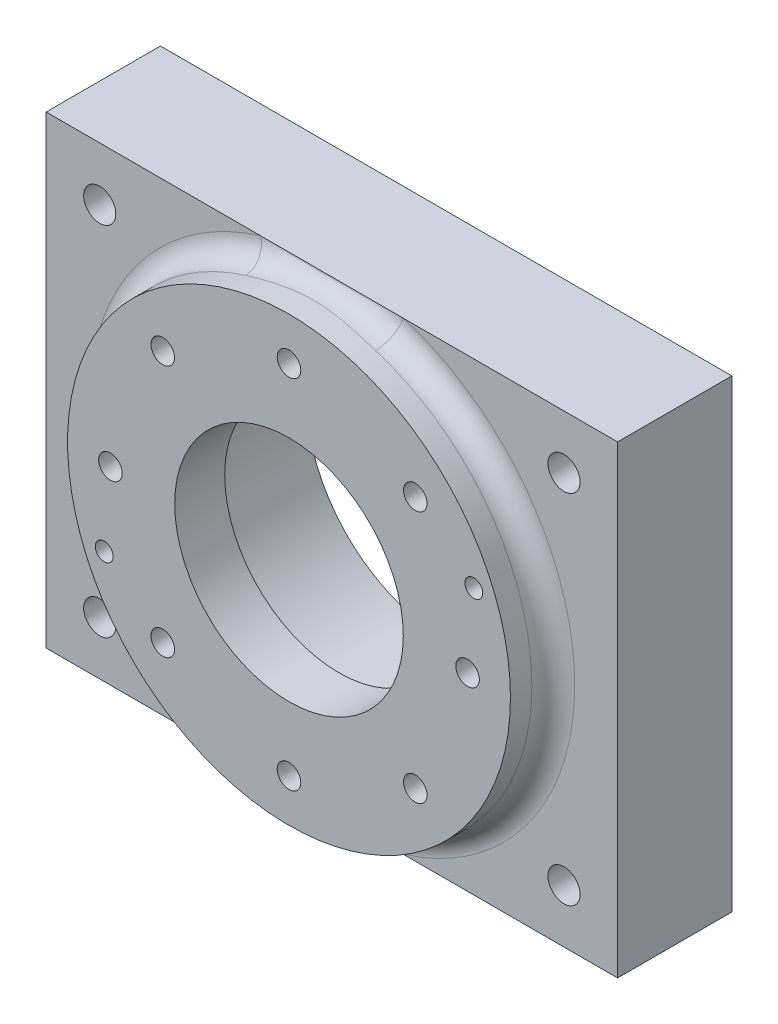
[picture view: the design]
ISO-10303-21;
HEADER;
FILE_DESCRIPTION(('STEP AP214'),'2;1');
FILE_NAME('part.step','',(''),(''),'','','');
FILE_SCHEMA(('AUTOMOTIVE_DESIGN { 1 0 10303 214 1 1 1 1 }'));
ENDSEC;
DATA;
#1=APPLICATION_CONTEXT('core data for automotive mechanical design processes');
#2=APPLICATION_PROTOCOL_DEFINITION('international standard','automotive_design',2000,#1);
#3=PRODUCT_CONTEXT('',#1,'mechanical');
#4=PRODUCT('Part','Part','',(#3));
#5=PRODUCT_RELATED_PRODUCT_CATEGORY('part','',(#4));
#6=PRODUCT_DEFINITION_FORMATION('','',#4);
#7=PRODUCT_DEFINITION_CONTEXT('part definition',#1,'design');
#8=PRODUCT_DEFINITION('design','',#6,#7);
#9=PRODUCT_DEFINITION_SHAPE('','',#8);
#10=(LENGTH_UNIT() NAMED_UNIT(*) SI_UNIT(.MILLI.,.METRE.));
#11=(NAMED_UNIT(*) PLANE_ANGLE_UNIT() SI_UNIT($,.RADIAN.));
#12=(NAMED_UNIT(*) SI_UNIT($,.STERADIAN.) SOLID_ANGLE_UNIT());
#13=UNCERTAINTY_MEASURE_WITH_UNIT(LENGTH_MEASURE(1.E-05),#10,'distance_accuracy_value','');
#14=(GEOMETRIC_REPRESENTATION_CONTEXT(3) GLOBAL_UNCERTAINTY_ASSIGNED_CONTEXT((#13)) GLOBAL_UNIT_ASSIGNED_CONTEXT((#10,
#11,#12)) REPRESENTATION_CONTEXT('',''));
#15=CARTESIAN_POINT('',(0.,0.,0.));
#16=DIRECTION('',(0.,0.,1.));
#17=DIRECTION('',(1.,0.,0.));
#18=AXIS2_PLACEMENT_3D('',#15,#16,#17);
#19=CARTESIAN_POINT('',(51.737253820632,21.430272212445,32.));
#20=DIRECTION('',(0.,0.,1.));
#21=DIRECTION('',(1.,0.,0.));
#22=AXIS2_PLACEMENT_3D('',#19,#20,#21);
#23=PLANE('',#22);
#24=CARTESIAN_POINT('',(51.737253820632,21.430272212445,32.));
#25=DIRECTION('',(0.,0.,1.));
#26=DIRECTION('',(1.,0.,0.));
#27=AXIS2_PLACEMENT_3D('',#24,#25,#26);
#28=CIRCLE('',#27,2.5);
#29=CARTESIAN_POINT('',(54.237253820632,21.430272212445,32.));
#30=VERTEX_POINT('',#29);
#31=EDGE_CURVE('E43',#30,#30,#28,.T.);
#32=ORIENTED_EDGE('',*,*,#31,.T.);
#33=EDGE_LOOP('',(#32));
#34=FACE_BOUND('',#33,.T.);
#35=ADVANCED_FACE('F15',(#34),#23,.T.);
#36=CARTESIAN_POINT('',(0.,0.,30.));
#37=DIRECTION('',(0.,0.,1.));
#38=DIRECTION('',(1.,0.,0.));
#39=AXIS2_PLACEMENT_3D('',#36,#37,#38);
#40=PLANE('',#39);
#41=CARTESIAN_POINT('',(0.,0.,30.));
#42=DIRECTION('',(0.,0.,1.));
#43=DIRECTION('',(1.,0.,0.));
#44=AXIS2_PLACEMENT_3D('',#41,#42,#43);
#45=CIRCLE('',#44,32.);
#46=CARTESIAN_POINT('',(32.,0.,30.));
#47=VERTEX_POINT('',#46);
#48=EDGE_CURVE('E363',#47,#47,#45,.T.);
#49=ORIENTED_EDGE('',*,*,#48,.T.);
#50=EDGE_LOOP('',(#49));
#51=FACE_BOUND('',#50,.T.);
#52=CARTESIAN_POINT('',(0.,0.,30.));
#53=DIRECTION('',(0.,0.,1.));
#54=DIRECTION('',(1.,0.,0.));
#55=AXIS2_PLACEMENT_3D('',#52,#53,#54);
#56=CIRCLE('',#55,39.003);
#57=CARTESIAN_POINT('',(39.003,0.,30.));
#58=VERTEX_POINT('',#57);
#59=EDGE_CURVE('E9',#58,#58,#56,.T.);
#60=ORIENTED_EDGE('',*,*,#59,.F.);
#61=EDGE_LOOP('',(#60));
#62=FACE_BOUND('',#61,.T.);
#63=ADVANCED_FACE('F875',(#51,#62),#40,.F.);
#64=CARTESIAN_POINT('',(-51.73725382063,-21.43027221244,32.));
#65=DIRECTION('',(0.,0.,1.));
#66=DIRECTION('',(1.,0.,0.));
#67=AXIS2_PLACEMENT_3D('',#64,#65,#66);
#68=PLANE('',#67);
#69=CARTESIAN_POINT('',(-51.73725382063,-21.43027221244,32.));
#70=DIRECTION('',(0.,0.,1.));
#71=DIRECTION('',(1.,0.,0.));
#72=AXIS2_PLACEMENT_3D('',#69,#70,#71);
#73=CIRCLE('',#72,2.5);
#74=CARTESIAN_POINT('',(-49.23725382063,-21.43027221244,32.));
#75=VERTEX_POINT('',#74);
#76=EDGE_CURVE('E131',#75,#75,#73,.T.);
#77=ORIENTED_EDGE('',*,*,#76,.T.);
#78=EDGE_LOOP('',(#77));
#79=FACE_BOUND('',#78,.T.);
#80=ADVANCED_FACE('F876',(#79),#68,.T.);
#81=CARTESIAN_POINT('',(0.,0.,26.));
#82=DIRECTION('',(0.,0.,1.));
#83=DIRECTION('',(1.,0.,0.));
#84=AXIS2_PLACEMENT_3D('',#81,#82,#83);
#85=CYLINDRICAL_SURFACE('',#84,39.003);
#86=DIRECTION('',(0.,0.,1.));
#87=VECTOR('',#86,1.);
#88=CARTESIAN_POINT('',(39.003,0.,26.));
#89=LINE('',#88,#87);
#90=CARTESIAN_POINT('',(39.003,0.,26.));
#91=VERTEX_POINT('',#90);
#92=EDGE_CURVE('E23',#91,#58,#89,.T.);
#93=ORIENTED_EDGE('',*,*,#92,.F.);
#94=CARTESIAN_POINT('',(0.,0.,26.));
#95=DIRECTION('',(0.,0.,1.));
#96=DIRECTION('',(1.,0.,0.));
#97=AXIS2_PLACEMENT_3D('',#94,#95,#96);
#98=CIRCLE('',#97,39.003);
#99=EDGE_CURVE('E293',#91,#91,#98,.T.);
#100=ORIENTED_EDGE('',*,*,#99,.F.);
#101=ORIENTED_EDGE('',*,*,#92,.T.);
#102=ORIENTED_EDGE('',*,*,#59,.T.);
#103=EDGE_LOOP('',(#93,#100,#101,#102));
#104=FACE_BOUND('',#103,.T.);
#105=ADVANCED_FACE('F882',(#104),#85,.F.);
#106=CARTESIAN_POINT('',(35.355339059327,35.355339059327,5.9));
#107=DIRECTION('',(0.,0.,1.));
#108=DIRECTION('',(1.,0.,0.));
#109=AXIS2_PLACEMENT_3D('',#106,#107,#108);
#110=CYLINDRICAL_SURFACE('',#109,3.3);
#111=CARTESIAN_POINT('',(35.355339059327,35.355339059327,6.1));
#112=DIRECTION('',(0.,0.,1.));
#113=DIRECTION('',(1.,0.,0.));
#114=AXIS2_PLACEMENT_3D('',#111,#112,#113);
#115=CIRCLE('',#114,3.3);
#116=CARTESIAN_POINT('',(38.655339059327,35.355339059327,6.1));
#117=VERTEX_POINT('',#116);
#118=EDGE_CURVE('E360',#117,#117,#115,.T.);
#119=ORIENTED_EDGE('',*,*,#118,.F.);
#120=DIRECTION('',(0.,0.,1.));
#121=VECTOR('',#120,1.);
#122=CARTESIAN_POINT('',(38.655339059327,35.355339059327,5.9));
#123=LINE('',#122,#121);
#124=CARTESIAN_POINT('',(38.655339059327,35.355339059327,44.));
#125=VERTEX_POINT('',#124);
#126=EDGE_CURVE('E142',#117,#125,#123,.T.);
#127=ORIENTED_EDGE('',*,*,#126,.T.);
#128=CARTESIAN_POINT('',(35.355339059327,35.355339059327,44.));
#129=DIRECTION('',(0.,0.,1.));
#130=DIRECTION('',(1.,0.,0.));
#131=AXIS2_PLACEMENT_3D('',#128,#129,#130);
#132=CIRCLE('',#131,3.3);
#133=EDGE_CURVE('E323',#125,#125,#132,.T.);
#134=ORIENTED_EDGE('',*,*,#133,.T.);
#135=ORIENTED_EDGE('',*,*,#126,.F.);
#136=EDGE_LOOP('',(#119,#127,#134,#135));
#137=FACE_BOUND('',#136,.T.);
#138=ADVANCED_FACE('F888',(#137),#110,.F.);
#139=CARTESIAN_POINT('',(51.737253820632,21.430272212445,32.));
#140=DIRECTION('',(0.,0.,1.));
#141=DIRECTION('',(1.,0.,0.));
#142=AXIS2_PLACEMENT_3D('',#139,#140,#141);
#143=CYLINDRICAL_SURFACE('',#142,2.5);
#144=DIRECTION('',(0.,0.,1.));
#145=VECTOR('',#144,1.);
#146=CARTESIAN_POINT('',(54.237253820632,21.430272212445,32.));
#147=LINE('',#146,#145);
#148=CARTESIAN_POINT('',(54.237253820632,21.430272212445,44.));
#149=VERTEX_POINT('',#148);
#150=EDGE_CURVE('E366',#30,#149,#147,.T.);
#151=ORIENTED_EDGE('',*,*,#150,.F.);
#152=ORIENTED_EDGE('',*,*,#31,.F.);
#153=ORIENTED_EDGE('',*,*,#150,.T.);
#154=CARTESIAN_POINT('',(51.737253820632,21.430272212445,44.));
#155=DIRECTION('',(0.,0.,1.));
#156=DIRECTION('',(1.,0.,0.));
#157=AXIS2_PLACEMENT_3D('',#154,#155,#156);
#158=CIRCLE('',#157,2.5);
#159=EDGE_CURVE('E330',#149,#149,#158,.T.);
#160=ORIENTED_EDGE('',*,*,#159,.T.);
#161=EDGE_LOOP('',(#151,#152,#153,#160));
#162=FACE_BOUND('',#161,.T.);
#163=ADVANCED_FACE('F883',(#162),#143,.F.);
#164=CARTESIAN_POINT('',(50.,0.,5.9));
#165=DIRECTION('',(0.,0.,1.));
#166=DIRECTION('',(1.,0.,0.));
#167=AXIS2_PLACEMENT_3D('',#164,#165,#166);
#168=CYLINDRICAL_SURFACE('',#167,3.3);
#169=CARTESIAN_POINT('',(50.,0.,6.1));
#170=DIRECTION('',(0.,0.,1.));
#171=DIRECTION('',(1.,0.,0.));
#172=AXIS2_PLACEMENT_3D('',#169,#170,#171);
#173=CIRCLE('',#172,3.3);
#174=CARTESIAN_POINT('',(53.3,0.,6.1));
#175=VERTEX_POINT('',#174);
#176=EDGE_CURVE('E300',#175,#175,#173,.T.);
#177=ORIENTED_EDGE('',*,*,#176,.F.);
#178=DIRECTION('',(0.,0.,1.));
#179=VECTOR('',#178,1.);
#180=CARTESIAN_POINT('',(53.3,0.,5.9));
#181=LINE('',#180,#179);
#182=CARTESIAN_POINT('',(53.3,0.,44.));
#183=VERTEX_POINT('',#182);
#184=EDGE_CURVE('E280',#175,#183,#181,.T.);
#185=ORIENTED_EDGE('',*,*,#184,.T.);
#186=CARTESIAN_POINT('',(50.,0.,44.));
#187=DIRECTION('',(0.,0.,1.));
#188=DIRECTION('',(1.,0.,0.));
#189=AXIS2_PLACEMENT_3D('',#186,#187,#188);
#190=CIRCLE('',#189,3.3);
#191=EDGE_CURVE('E321',#183,#183,#190,.T.);
#192=ORIENTED_EDGE('',*,*,#191,.T.);
#193=ORIENTED_EDGE('',*,*,#184,.F.);
#194=EDGE_LOOP('',(#177,#185,#192,#193));
#195=FACE_BOUND('',#194,.T.);
#196=ADVANCED_FACE('F889',(#195),#168,.F.);
#197=CARTESIAN_POINT('',(0.,50.,5.9));
#198=DIRECTION('',(0.,0.,1.));
#199=DIRECTION('',(1.,0.,0.));
#200=AXIS2_PLACEMENT_3D('',#197,#198,#199);
#201=CYLINDRICAL_SURFACE('',#200,3.3);
#202=CARTESIAN_POINT('',(0.,50.,6.1));
#203=DIRECTION('',(0.,0.,1.));
#204=DIRECTION('',(1.,0.,0.));
#205=AXIS2_PLACEMENT_3D('',#202,#203,#204);
#206=CIRCLE('',#205,3.3);
#207=CARTESIAN_POINT('',(3.3,50.,6.1));
#208=VERTEX_POINT('',#207);
#209=EDGE_CURVE('E352',#208,#208,#206,.T.);
#210=ORIENTED_EDGE('',*,*,#209,.F.);
#211=DIRECTION('',(0.,0.,1.));
#212=VECTOR('',#211,1.);
#213=CARTESIAN_POINT('',(3.3,50.,5.9));
#214=LINE('',#213,#212);
#215=CARTESIAN_POINT('',(3.3,50.,44.));
#216=VERTEX_POINT('',#215);
#217=EDGE_CURVE('E272',#208,#216,#214,.T.);
#218=ORIENTED_EDGE('',*,*,#217,.T.);
#219=CARTESIAN_POINT('',(0.,50.,44.));
#220=DIRECTION('',(0.,0.,1.));
#221=DIRECTION('',(1.,0.,0.));
#222=AXIS2_PLACEMENT_3D('',#219,#220,#221);
#223=CIRCLE('',#222,3.3);
#224=EDGE_CURVE('E320',#216,#216,#223,.T.);
#225=ORIENTED_EDGE('',*,*,#224,.T.);
#226=ORIENTED_EDGE('',*,*,#217,.F.);
#227=EDGE_LOOP('',(#210,#218,#225,#226));
#228=FACE_BOUND('',#227,.T.);
#229=ADVANCED_FACE('F893',(#228),#201,.F.);
#230=CARTESIAN_POINT('',(-35.35533905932,35.355339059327,5.9));
#231=DIRECTION('',(0.,0.,1.));
#232=DIRECTION('',(1.,0.,0.));
#233=AXIS2_PLACEMENT_3D('',#230,#231,#232);
#234=CYLINDRICAL_SURFACE('',#233,3.3);
#235=CARTESIAN_POINT('',(-35.35533905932,35.355339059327,6.1));
#236=DIRECTION('',(0.,0.,1.));
#237=DIRECTION('',(1.,0.,0.));
#238=AXIS2_PLACEMENT_3D('',#235,#236,#237);
#239=CIRCLE('',#238,3.3);
#240=CARTESIAN_POINT('',(-32.05533905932,35.355339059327,6.1));
#241=VERTEX_POINT('',#240);
#242=EDGE_CURVE('E297',#241,#241,#239,.T.);
#243=ORIENTED_EDGE('',*,*,#242,.F.);
#244=DIRECTION('',(0.,0.,1.));
#245=VECTOR('',#244,1.);
#246=CARTESIAN_POINT('',(-32.05533905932,35.355339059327,5.9));
#247=LINE('',#246,#245);
#248=CARTESIAN_POINT('',(-32.05533905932,35.355339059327,44.));
#249=VERTEX_POINT('',#248);
#250=EDGE_CURVE('E279',#241,#249,#247,.T.);
#251=ORIENTED_EDGE('',*,*,#250,.T.);
#252=CARTESIAN_POINT('',(-35.35533905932,35.355339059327,44.));
#253=DIRECTION('',(0.,0.,1.));
#254=DIRECTION('',(1.,0.,0.));
#255=AXIS2_PLACEMENT_3D('',#252,#253,#254);
#256=CIRCLE('',#255,3.3);
#257=EDGE_CURVE('E325',#249,#249,#256,.T.);
#258=ORIENTED_EDGE('',*,*,#257,.T.);
#259=ORIENTED_EDGE('',*,*,#250,.F.);
#260=EDGE_LOOP('',(#243,#251,#258,#259));
#261=FACE_BOUND('',#260,.T.);
#262=ADVANCED_FACE('F890',(#261),#234,.F.);
#263=CARTESIAN_POINT('',(0.,0.,30.));
#264=DIRECTION('',(0.,0.,1.));
#265=DIRECTION('',(1.,0.,0.));
#266=AXIS2_PLACEMENT_3D('',#263,#264,#265);
#267=CYLINDRICAL_SURFACE('',#266,32.);
#268=DIRECTION('',(0.,0.,1.));
#269=VECTOR('',#268,1.);
#270=CARTESIAN_POINT('',(32.,0.,30.));
#271=LINE('',#270,#269);
#272=CARTESIAN_POINT('',(32.,0.,44.));
#273=VERTEX_POINT('',#272);
#274=EDGE_CURVE('E365',#47,#273,#271,.T.);
#275=ORIENTED_EDGE('',*,*,#274,.F.);
#276=ORIENTED_EDGE('',*,*,#48,.F.);
#277=ORIENTED_EDGE('',*,*,#274,.T.);
#278=CARTESIAN_POINT('',(0.,0.,44.));
#279=DIRECTION('',(0.,0.,1.));
#280=DIRECTION('',(1.,0.,0.));
#281=AXIS2_PLACEMENT_3D('',#278,#279,#280);
#282=CIRCLE('',#281,32.);
#283=EDGE_CURVE('E316',#273,#273,#282,.T.);
#284=ORIENTED_EDGE('',*,*,#283,.T.);
#285=EDGE_LOOP('',(#275,#276,#277,#284));
#286=FACE_BOUND('',#285,.T.);
#287=ADVANCED_FACE('F434',(#286),#267,.F.);
#288=CARTESIAN_POINT('',(-50.,0.,5.9));
#289=DIRECTION('',(0.,0.,1.));
#290=DIRECTION('',(1.,0.,0.));
#291=AXIS2_PLACEMENT_3D('',#288,#289,#290);
#292=CYLINDRICAL_SURFACE('',#291,3.3);
#293=CARTESIAN_POINT('',(-50.,0.,6.1));
#294=DIRECTION('',(0.,0.,1.));
#295=DIRECTION('',(1.,0.,0.));
#296=AXIS2_PLACEMENT_3D('',#293,#294,#295);
#297=CIRCLE('',#296,3.3);
#298=CARTESIAN_POINT('',(-46.7,0.,6.1));
#299=VERTEX_POINT('',#298);
#300=EDGE_CURVE('E338',#299,#299,#297,.T.);
#301=ORIENTED_EDGE('',*,*,#300,.F.);
#302=DIRECTION('',(0.,0.,1.));
#303=VECTOR('',#302,1.);
#304=CARTESIAN_POINT('',(-46.7,0.,5.9));
#305=LINE('',#304,#303);
#306=CARTESIAN_POINT('',(-46.7,0.,44.));
#307=VERTEX_POINT('',#306);
#308=EDGE_CURVE('E343',#299,#307,#305,.T.);
#309=ORIENTED_EDGE('',*,*,#308,.T.);
#310=CARTESIAN_POINT('',(-50.,0.,44.));
#311=DIRECTION('',(0.,0.,1.));
#312=DIRECTION('',(1.,0.,0.));
#313=AXIS2_PLACEMENT_3D('',#310,#311,#312);
#314=CIRCLE('',#313,3.3);
#315=EDGE_CURVE('E307',#307,#307,#314,.T.);
#316=ORIENTED_EDGE('',*,*,#315,.T.);
#317=ORIENTED_EDGE('',*,*,#308,.F.);
#318=EDGE_LOOP('',(#301,#309,#316,#317));
#319=FACE_BOUND('',#318,.T.);
#320=ADVANCED_FACE('F896',(#319),#292,.F.);
#321=CARTESIAN_POINT('',(35.355339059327,-35.35533905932,5.9));
#322=DIRECTION('',(0.,0.,1.));
#323=DIRECTION('',(1.,0.,0.));
#324=AXIS2_PLACEMENT_3D('',#321,#322,#323);
#325=CYLINDRICAL_SURFACE('',#324,3.3);
#326=CARTESIAN_POINT('',(35.355339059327,-35.35533905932,6.1));
#327=DIRECTION('',(0.,0.,1.));
#328=DIRECTION('',(1.,0.,0.));
#329=AXIS2_PLACEMENT_3D('',#326,#327,#328);
#330=CIRCLE('',#329,3.3);
#331=CARTESIAN_POINT('',(38.655339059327,-35.35533905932,6.1));
#332=VERTEX_POINT('',#331);
#333=EDGE_CURVE('E333',#332,#332,#330,.T.);
#334=ORIENTED_EDGE('',*,*,#333,.F.);
#335=DIRECTION('',(0.,0.,1.));
#336=VECTOR('',#335,1.);
#337=CARTESIAN_POINT('',(38.655339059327,-35.35533905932,5.9));
#338=LINE('',#337,#336);
#339=CARTESIAN_POINT('',(38.655339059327,-35.35533905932,44.));
#340=VERTEX_POINT('',#339);
#341=EDGE_CURVE('E340',#332,#340,#338,.T.);
#342=ORIENTED_EDGE('',*,*,#341,.T.);
#343=CARTESIAN_POINT('',(35.355339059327,-35.35533905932,44.));
#344=DIRECTION('',(0.,0.,1.));
#345=DIRECTION('',(1.,0.,0.));
#346=AXIS2_PLACEMENT_3D('',#343,#344,#345);
#347=CIRCLE('',#346,3.3);
#348=EDGE_CURVE('E304',#340,#340,#347,.T.);
#349=ORIENTED_EDGE('',*,*,#348,.T.);
#350=ORIENTED_EDGE('',*,*,#341,.F.);
#351=EDGE_LOOP('',(#334,#342,#349,#350));
#352=FACE_BOUND('',#351,.T.);
#353=ADVANCED_FACE('F899',(#352),#325,.F.);
#354=CARTESIAN_POINT('',(-51.73725382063,-21.43027221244,32.));
#355=DIRECTION('',(0.,0.,1.));
#356=DIRECTION('',(1.,0.,0.));
#357=AXIS2_PLACEMENT_3D('',#354,#355,#356);
#358=CYLINDRICAL_SURFACE('',#357,2.5);
#359=DIRECTION('',(0.,0.,1.));
#360=VECTOR('',#359,1.);
#361=CARTESIAN_POINT('',(-49.23725382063,-21.43027221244,32.));
#362=LINE('',#361,#360);
#363=CARTESIAN_POINT('',(-49.23725382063,-21.43027221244,44.));
#364=VERTEX_POINT('',#363);
#365=EDGE_CURVE('E310',#75,#364,#362,.T.);
#366=ORIENTED_EDGE('',*,*,#365,.F.);
#367=ORIENTED_EDGE('',*,*,#76,.F.);
#368=ORIENTED_EDGE('',*,*,#365,.T.);
#369=CARTESIAN_POINT('',(-51.73725382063,-21.43027221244,44.));
#370=DIRECTION('',(0.,0.,1.));
#371=DIRECTION('',(1.,0.,0.));
#372=AXIS2_PLACEMENT_3D('',#369,#370,#371);
#373=CIRCLE('',#372,2.5);
#374=EDGE_CURVE('E306',#364,#364,#373,.T.);
#375=ORIENTED_EDGE('',*,*,#374,.T.);
#376=EDGE_LOOP('',(#366,#367,#368,#375));
#377=FACE_BOUND('',#376,.T.);
#378=ADVANCED_FACE('F903',(#377),#358,.F.);
#379=CARTESIAN_POINT('',(0.,-50.,5.9));
#380=DIRECTION('',(0.,0.,1.));
#381=DIRECTION('',(1.,0.,0.));
#382=AXIS2_PLACEMENT_3D('',#379,#380,#381);
#383=CYLINDRICAL_SURFACE('',#382,3.3);
#384=CARTESIAN_POINT('',(0.,-50.,6.1));
#385=DIRECTION('',(0.,0.,1.));
#386=DIRECTION('',(1.,0.,0.));
#387=AXIS2_PLACEMENT_3D('',#384,#385,#386);
#388=CIRCLE('',#387,3.3);
#389=CARTESIAN_POINT('',(3.3,-50.,6.1));
#390=VERTEX_POINT('',#389);
#391=EDGE_CURVE('E332',#390,#390,#388,.T.);
#392=ORIENTED_EDGE('',*,*,#391,.F.);
#393=DIRECTION('',(0.,0.,1.));
#394=VECTOR('',#393,1.);
#395=CARTESIAN_POINT('',(3.3,-50.,5.9));
#396=LINE('',#395,#394);
#397=CARTESIAN_POINT('',(3.3,-50.,44.));
#398=VERTEX_POINT('',#397);
#399=EDGE_CURVE('E315',#390,#398,#396,.T.);
#400=ORIENTED_EDGE('',*,*,#399,.T.);
#401=CARTESIAN_POINT('',(0.,-50.,44.));
#402=DIRECTION('',(0.,0.,1.));
#403=DIRECTION('',(1.,0.,0.));
#404=AXIS2_PLACEMENT_3D('',#401,#402,#403);
#405=CIRCLE('',#404,3.3);
#406=EDGE_CURVE('E454',#398,#398,#405,.T.);
#407=ORIENTED_EDGE('',*,*,#406,.T.);
#408=ORIENTED_EDGE('',*,*,#399,.F.);
#409=EDGE_LOOP('',(#392,#400,#407,#408));
#410=FACE_BOUND('',#409,.T.);
#411=ADVANCED_FACE('F909',(#410),#383,.F.);
#412=CARTESIAN_POINT('',(-35.35533905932,-35.35533905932,5.9));
#413=DIRECTION('',(0.,0.,1.));
#414=DIRECTION('',(1.,0.,0.));
#415=AXIS2_PLACEMENT_3D('',#412,#413,#414);
#416=CYLINDRICAL_SURFACE('',#415,3.3);
#417=CARTESIAN_POINT('',(-35.35533905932,-35.35533905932,6.1));
#418=DIRECTION('',(0.,0.,1.));
#419=DIRECTION('',(1.,0.,0.));
#420=AXIS2_PLACEMENT_3D('',#417,#418,#419);
#421=CIRCLE('',#420,3.3);
#422=CARTESIAN_POINT('',(-32.05533905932,-35.35533905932,6.1));
#423=VERTEX_POINT('',#422);
#424=EDGE_CURVE('E326',#423,#423,#421,.T.);
#425=ORIENTED_EDGE('',*,*,#424,.F.);
#426=DIRECTION('',(0.,0.,1.));
#427=VECTOR('',#426,1.);
#428=CARTESIAN_POINT('',(-32.05533905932,-35.35533905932,5.9));
#429=LINE('',#428,#427);
#430=CARTESIAN_POINT('',(-32.05533905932,-35.35533905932,44.));
#431=VERTEX_POINT('',#430);
#432=EDGE_CURVE('E358',#423,#431,#429,.T.);
#433=ORIENTED_EDGE('',*,*,#432,.T.);
#434=CARTESIAN_POINT('',(-35.35533905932,-35.35533905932,44.));
#435=DIRECTION('',(0.,0.,1.));
#436=DIRECTION('',(1.,0.,0.));
#437=AXIS2_PLACEMENT_3D('',#434,#435,#436);
#438=CIRCLE('',#437,3.3);
#439=EDGE_CURVE('E305',#431,#431,#438,.T.);
#440=ORIENTED_EDGE('',*,*,#439,.T.);
#441=ORIENTED_EDGE('',*,*,#432,.F.);
#442=EDGE_LOOP('',(#425,#433,#440,#441));
#443=FACE_BOUND('',#442,.T.);
#444=ADVANCED_FACE('F911',(#443),#416,.F.);
#445=CARTESIAN_POINT('',(35.355339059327,35.355339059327,6.1));
#446=DIRECTION('',(0.,0.,1.));
#447=DIRECTION('',(1.,0.,0.));
#448=AXIS2_PLACEMENT_3D('',#445,#446,#447);
#449=PLANE('',#448);
#450=ORIENTED_EDGE('',*,*,#118,.T.);
#451=EDGE_LOOP('',(#450));
#452=FACE_BOUND('',#451,.T.);
#453=CARTESIAN_POINT('',(35.355339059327,35.355339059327,6.1));
#454=DIRECTION('',(0.,0.,1.));
#455=DIRECTION('',(1.,0.,0.));
#456=AXIS2_PLACEMENT_3D('',#453,#454,#455);
#457=CIRCLE('',#456,5.5);
#458=CARTESIAN_POINT('',(40.855339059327,35.355339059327,6.1));
#459=VERTEX_POINT('',#458);
#460=EDGE_CURVE('E298',#459,#459,#457,.T.);
#461=ORIENTED_EDGE('',*,*,#460,.F.);
#462=EDGE_LOOP('',(#461));
#463=FACE_BOUND('',#462,.T.);
#464=ADVANCED_FACE('F918',(#452,#463),#449,.F.);
#465=CARTESIAN_POINT('',(0.,50.,6.1));
#466=DIRECTION('',(0.,0.,1.));
#467=DIRECTION('',(1.,0.,0.));
#468=AXIS2_PLACEMENT_3D('',#465,#466,#467);
#469=PLANE('',#468);
#470=ORIENTED_EDGE('',*,*,#209,.T.);
#471=EDGE_LOOP('',(#470));
#472=FACE_BOUND('',#471,.T.);
#473=CARTESIAN_POINT('',(0.,50.,6.1));
#474=DIRECTION('',(0.,0.,1.));
#475=DIRECTION('',(1.,0.,0.));
#476=AXIS2_PLACEMENT_3D('',#473,#474,#475);
#477=CIRCLE('',#476,5.5);
#478=CARTESIAN_POINT('',(5.5,50.,6.1));
#479=VERTEX_POINT('',#478);
#480=EDGE_CURVE('E276',#479,#479,#477,.T.);
#481=ORIENTED_EDGE('',*,*,#480,.F.);
#482=EDGE_LOOP('',(#481));
#483=FACE_BOUND('',#482,.T.);
#484=ADVANCED_FACE('F968',(#472,#483),#469,.F.);
#485=CARTESIAN_POINT('',(16.838071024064,40.650699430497,12.));
#486=DIRECTION('',(0.,0.,1.));
#487=DIRECTION('',(1.,0.,0.));
#488=AXIS2_PLACEMENT_3D('',#485,#486,#487);
#489=PLANE('',#488);
#490=CARTESIAN_POINT('',(16.838071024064,40.650699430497,12.));
#491=DIRECTION('',(0.,0.,1.));
#492=DIRECTION('',(1.,0.,0.));
#493=AXIS2_PLACEMENT_3D('',#490,#491,#492);
#494=CIRCLE('',#493,1.65);
#495=CARTESIAN_POINT('',(18.488071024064,40.650699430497,12.));
#496=VERTEX_POINT('',#495);
#497=EDGE_CURVE('E288',#496,#496,#494,.T.);
#498=ORIENTED_EDGE('',*,*,#497,.F.);
#499=EDGE_LOOP('',(#498));
#500=FACE_BOUND('',#499,.T.);
#501=ADVANCED_FACE('F925',(#500),#489,.F.);
#502=CARTESIAN_POINT('',(40.650699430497,16.838071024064,12.));
#503=DIRECTION('',(0.,0.,1.));
#504=DIRECTION('',(1.,0.,0.));
#505=AXIS2_PLACEMENT_3D('',#502,#503,#504);
#506=PLANE('',#505);
#507=CARTESIAN_POINT('',(40.650699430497,16.838071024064,12.));
#508=DIRECTION('',(0.,0.,1.));
#509=DIRECTION('',(1.,0.,0.));
#510=AXIS2_PLACEMENT_3D('',#507,#508,#509);
#511=CIRCLE('',#510,1.65);
#512=CARTESIAN_POINT('',(42.300699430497,16.838071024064,12.));
#513=VERTEX_POINT('',#512);
#514=EDGE_CURVE('E287',#513,#513,#511,.T.);
#515=ORIENTED_EDGE('',*,*,#514,.F.);
#516=EDGE_LOOP('',(#515));
#517=FACE_BOUND('',#516,.T.);
#518=ADVANCED_FACE('F916',(#517),#506,.F.);
#519=CARTESIAN_POINT('',(50.,0.,6.1));
#520=DIRECTION('',(0.,0.,1.));
#521=DIRECTION('',(1.,0.,0.));
#522=AXIS2_PLACEMENT_3D('',#519,#520,#521);
#523=PLANE('',#522);
#524=ORIENTED_EDGE('',*,*,#176,.T.);
#525=EDGE_LOOP('',(#524));
#526=FACE_BOUND('',#525,.T.);
#527=CARTESIAN_POINT('',(50.,0.,6.1));
#528=DIRECTION('',(0.,0.,1.));
#529=DIRECTION('',(1.,0.,0.));
#530=AXIS2_PLACEMENT_3D('',#527,#528,#529);
#531=CIRCLE('',#530,5.5);
#532=CARTESIAN_POINT('',(55.5,0.,6.1));
#533=VERTEX_POINT('',#532);
#534=EDGE_CURVE('E497',#533,#533,#531,.T.);
#535=ORIENTED_EDGE('',*,*,#534,.F.);
#536=EDGE_LOOP('',(#535));
#537=FACE_BOUND('',#536,.T.);
#538=ADVANCED_FACE('F921',(#526,#537),#523,.F.);
#539=CARTESIAN_POINT('',(0.,0.,26.));
#540=DIRECTION('',(0.,0.,1.));
#541=DIRECTION('',(1.,0.,0.));
#542=AXIS2_PLACEMENT_3D('',#539,#540,#541);
#543=PLANE('',#542);
#544=ORIENTED_EDGE('',*,*,#99,.T.);
#545=EDGE_LOOP('',(#544));
#546=FACE_BOUND('',#545,.T.);
#547=CARTESIAN_POINT('',(0.,0.,26.));
#548=DIRECTION('',(0.,0.,1.));
#549=DIRECTION('',(1.,0.,0.));
#550=AXIS2_PLACEMENT_3D('',#547,#548,#549);
#551=CIRCLE('',#550,39.1);
#552=CARTESIAN_POINT('',(39.1,0.,26.));
#553=VERTEX_POINT('',#552);
#554=EDGE_CURVE('E267',#553,#553,#551,.T.);
#555=ORIENTED_EDGE('',*,*,#554,.F.);
#556=EDGE_LOOP('',(#555));
#557=FACE_BOUND('',#556,.T.);
#558=ADVANCED_FACE('F922',(#546,#557),#543,.F.);
#559=CARTESIAN_POINT('',(-16.83807102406,40.650699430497,12.));
#560=DIRECTION('',(0.,0.,1.));
#561=DIRECTION('',(1.,0.,0.));
#562=AXIS2_PLACEMENT_3D('',#559,#560,#561);
#563=PLANE('',#562);
#564=CARTESIAN_POINT('',(-16.83807102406,40.650699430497,12.));
#565=DIRECTION('',(0.,0.,1.));
#566=DIRECTION('',(1.,0.,0.));
#567=AXIS2_PLACEMENT_3D('',#564,#565,#566);
#568=CIRCLE('',#567,1.65);
#569=CARTESIAN_POINT('',(-15.18807102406,40.650699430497,12.));
#570=VERTEX_POINT('',#569);
#571=EDGE_CURVE('E261',#570,#570,#568,.T.);
#572=ORIENTED_EDGE('',*,*,#571,.F.);
#573=EDGE_LOOP('',(#572));
#574=FACE_BOUND('',#573,.T.);
#575=ADVANCED_FACE('F930',(#574),#563,.F.);
#576=CARTESIAN_POINT('',(-35.35533905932,35.355339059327,6.1));
#577=DIRECTION('',(0.,0.,1.));
#578=DIRECTION('',(1.,0.,0.));
#579=AXIS2_PLACEMENT_3D('',#576,#577,#578);
#580=PLANE('',#579);
#581=ORIENTED_EDGE('',*,*,#242,.T.);
#582=EDGE_LOOP('',(#581));
#583=FACE_BOUND('',#582,.T.);
#584=CARTESIAN_POINT('',(-35.35533905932,35.355339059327,6.1));
#585=DIRECTION('',(0.,0.,1.));
#586=DIRECTION('',(1.,0.,0.));
#587=AXIS2_PLACEMENT_3D('',#584,#585,#586);
#588=CIRCLE('',#587,5.5);
#589=CARTESIAN_POINT('',(-29.85533905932,35.355339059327,6.1));
#590=VERTEX_POINT('',#589);
#591=EDGE_CURVE('E247',#590,#590,#588,.T.);
#592=ORIENTED_EDGE('',*,*,#591,.F.);
#593=EDGE_LOOP('',(#592));
#594=FACE_BOUND('',#593,.T.);
#595=ADVANCED_FACE('F931',(#583,#594),#580,.F.);
#596=CARTESIAN_POINT('',(-40.65069943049,16.838071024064,12.));
#597=DIRECTION('',(0.,0.,1.));
#598=DIRECTION('',(1.,0.,0.));
#599=AXIS2_PLACEMENT_3D('',#596,#597,#598);
#600=PLANE('',#599);
#601=CARTESIAN_POINT('',(-40.65069943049,16.838071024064,12.));
#602=DIRECTION('',(0.,0.,1.));
#603=DIRECTION('',(1.,0.,0.));
#604=AXIS2_PLACEMENT_3D('',#601,#602,#603);
#605=CIRCLE('',#604,1.65);
#606=CARTESIAN_POINT('',(-39.00069943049,16.838071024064,12.));
#607=VERTEX_POINT('',#606);
#608=EDGE_CURVE('E237',#607,#607,#605,.T.);
#609=ORIENTED_EDGE('',*,*,#608,.F.);
#610=EDGE_LOOP('',(#609));
#611=FACE_BOUND('',#610,.T.);
#612=ADVANCED_FACE('F934',(#611),#600,.F.);
#613=CARTESIAN_POINT('',(-50.,0.,6.1));
#614=DIRECTION('',(0.,0.,1.));
#615=DIRECTION('',(1.,0.,0.));
#616=AXIS2_PLACEMENT_3D('',#613,#614,#615);
#617=PLANE('',#616);
#618=ORIENTED_EDGE('',*,*,#300,.T.);
#619=EDGE_LOOP('',(#618));
#620=FACE_BOUND('',#619,.T.);
#621=CARTESIAN_POINT('',(-50.,0.,6.1));
#622=DIRECTION('',(0.,0.,1.));
#623=DIRECTION('',(1.,0.,0.));
#624=AXIS2_PLACEMENT_3D('',#621,#622,#623);
#625=CIRCLE('',#624,5.5);
#626=CARTESIAN_POINT('',(-44.5,0.,6.1));
#627=VERTEX_POINT('',#626);
#628=EDGE_CURVE('E389',#627,#627,#625,.T.);
#629=ORIENTED_EDGE('',*,*,#628,.F.);
#630=EDGE_LOOP('',(#629));
#631=FACE_BOUND('',#630,.T.);
#632=ADVANCED_FACE('F936',(#620,#631),#617,.F.);
#633=CARTESIAN_POINT('',(40.650699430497,-16.83807102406,12.));
#634=DIRECTION('',(0.,0.,1.));
#635=DIRECTION('',(1.,0.,0.));
#636=AXIS2_PLACEMENT_3D('',#633,#634,#635);
#637=PLANE('',#636);
#638=CARTESIAN_POINT('',(40.650699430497,-16.83807102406,12.));
#639=DIRECTION('',(0.,0.,1.));
#640=DIRECTION('',(1.,0.,0.));
#641=AXIS2_PLACEMENT_3D('',#638,#639,#640);
#642=CIRCLE('',#641,1.65);
#643=CARTESIAN_POINT('',(42.300699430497,-16.83807102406,12.));
#644=VERTEX_POINT('',#643);
#645=EDGE_CURVE('E398',#644,#644,#642,.T.);
#646=ORIENTED_EDGE('',*,*,#645,.F.);
#647=EDGE_LOOP('',(#646));
#648=FACE_BOUND('',#647,.T.);
#649=ADVANCED_FACE('F944',(#648),#637,.F.);
#650=CARTESIAN_POINT('',(35.355339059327,-35.35533905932,6.1));
#651=DIRECTION('',(0.,0.,1.));
#652=DIRECTION('',(1.,0.,0.));
#653=AXIS2_PLACEMENT_3D('',#650,#651,#652);
#654=PLANE('',#653);
#655=ORIENTED_EDGE('',*,*,#333,.T.);
#656=EDGE_LOOP('',(#655));
#657=FACE_BOUND('',#656,.T.);
#658=CARTESIAN_POINT('',(35.355339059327,-35.35533905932,6.1));
#659=DIRECTION('',(0.,0.,1.));
#660=DIRECTION('',(1.,0.,0.));
#661=AXIS2_PLACEMENT_3D('',#658,#659,#660);
#662=CIRCLE('',#661,5.5);
#663=CARTESIAN_POINT('',(40.855339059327,-35.35533905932,6.1));
#664=VERTEX_POINT('',#663);
#665=EDGE_CURVE('E419',#664,#664,#662,.T.);
#666=ORIENTED_EDGE('',*,*,#665,.F.);
#667=EDGE_LOOP('',(#666));
#668=FACE_BOUND('',#667,.T.);
#669=ADVANCED_FACE('F949',(#657,#668),#654,.F.);
#670=CARTESIAN_POINT('',(16.838071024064,-40.65069943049,12.));
#671=DIRECTION('',(0.,0.,1.));
#672=DIRECTION('',(1.,0.,0.));
#673=AXIS2_PLACEMENT_3D('',#670,#671,#672);
#674=PLANE('',#673);
#675=CARTESIAN_POINT('',(16.838071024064,-40.65069943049,12.));
#676=DIRECTION('',(0.,0.,1.));
#677=DIRECTION('',(1.,0.,0.));
#678=AXIS2_PLACEMENT_3D('',#675,#676,#677);
#679=CIRCLE('',#678,1.65);
#680=CARTESIAN_POINT('',(18.488071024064,-40.65069943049,12.));
#681=VERTEX_POINT('',#680);
#682=EDGE_CURVE('E407',#681,#681,#679,.T.);
#683=ORIENTED_EDGE('',*,*,#682,.F.);
#684=EDGE_LOOP('',(#683));
#685=FACE_BOUND('',#684,.T.);
#686=ADVANCED_FACE('F866',(#685),#674,.F.);
#687=CARTESIAN_POINT('',(-40.65069943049,-16.83807102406,12.));
#688=DIRECTION('',(0.,0.,1.));
#689=DIRECTION('',(1.,0.,0.));
#690=AXIS2_PLACEMENT_3D('',#687,#688,#689);
#691=PLANE('',#690);
#692=CARTESIAN_POINT('',(-40.65069943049,-16.83807102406,12.));
#693=DIRECTION('',(0.,0.,1.));
#694=DIRECTION('',(1.,0.,0.));
#695=AXIS2_PLACEMENT_3D('',#692,#693,#694);
#696=CIRCLE('',#695,1.65);
#697=CARTESIAN_POINT('',(-39.00069943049,-16.83807102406,12.));
#698=VERTEX_POINT('',#697);
#699=EDGE_CURVE('E408',#698,#698,#696,.T.);
#700=ORIENTED_EDGE('',*,*,#699,.F.);
#701=EDGE_LOOP('',(#700));
#702=FACE_BOUND('',#701,.T.);
#703=ADVANCED_FACE('F857',(#702),#691,.F.);
#704=CARTESIAN_POINT('',(-16.83807102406,-40.65069943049,12.));
#705=DIRECTION('',(0.,0.,1.));
#706=DIRECTION('',(1.,0.,0.));
#707=AXIS2_PLACEMENT_3D('',#704,#705,#706);
#708=PLANE('',#707);
#709=CARTESIAN_POINT('',(-16.83807102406,-40.65069943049,12.));
#710=DIRECTION('',(0.,0.,1.));
#711=DIRECTION('',(1.,0.,0.));
#712=AXIS2_PLACEMENT_3D('',#709,#710,#711);
#713=CIRCLE('',#712,1.65);
#714=CARTESIAN_POINT('',(-15.18807102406,-40.65069943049,12.));
#715=VERTEX_POINT('',#714);
#716=EDGE_CURVE('E403',#715,#715,#713,.T.);
#717=ORIENTED_EDGE('',*,*,#716,.F.);
#718=EDGE_LOOP('',(#717));
#719=FACE_BOUND('',#718,.T.);
#720=ADVANCED_FACE('F851',(#719),#708,.F.);
#721=CARTESIAN_POINT('',(0.,-50.,6.1));
#722=DIRECTION('',(0.,0.,1.));
#723=DIRECTION('',(1.,0.,0.));
#724=AXIS2_PLACEMENT_3D('',#721,#722,#723);
#725=PLANE('',#724);
#726=ORIENTED_EDGE('',*,*,#391,.T.);
#727=EDGE_LOOP('',(#726));
#728=FACE_BOUND('',#727,.T.);
#729=CARTESIAN_POINT('',(0.,-50.,6.1));
#730=DIRECTION('',(0.,0.,1.));
#731=DIRECTION('',(1.,0.,0.));
#732=AXIS2_PLACEMENT_3D('',#729,#730,#731);
#733=CIRCLE('',#732,5.5);
#734=CARTESIAN_POINT('',(5.5,-50.,6.1));
#735=VERTEX_POINT('',#734);
#736=EDGE_CURVE('E394',#735,#735,#733,.T.);
#737=ORIENTED_EDGE('',*,*,#736,.F.);
#738=EDGE_LOOP('',(#737));
#739=FACE_BOUND('',#738,.T.);
#740=ADVANCED_FACE('F858',(#728,#739),#725,.F.);
#741=CARTESIAN_POINT('',(-35.35533905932,-35.35533905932,6.1));
#742=DIRECTION('',(0.,0.,1.));
#743=DIRECTION('',(1.,0.,0.));
#744=AXIS2_PLACEMENT_3D('',#741,#742,#743);
#745=PLANE('',#744);
#746=ORIENTED_EDGE('',*,*,#424,.T.);
#747=EDGE_LOOP('',(#746));
#748=FACE_BOUND('',#747,.T.);
#749=CARTESIAN_POINT('',(-35.35533905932,-35.35533905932,6.1));
#750=DIRECTION('',(0.,0.,1.));
#751=DIRECTION('',(1.,0.,0.));
#752=AXIS2_PLACEMENT_3D('',#749,#750,#751);
#753=CIRCLE('',#752,5.5);
#754=CARTESIAN_POINT('',(-29.85533905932,-35.35533905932,6.1));
#755=VERTEX_POINT('',#754);
#756=EDGE_CURVE('E383',#755,#755,#753,.T.);
#757=ORIENTED_EDGE('',*,*,#756,.F.);
#758=EDGE_LOOP('',(#757));
#759=FACE_BOUND('',#758,.T.);
#760=ADVANCED_FACE('F445',(#748,#759),#745,.F.);
#761=CARTESIAN_POINT('',(0.,0.,44.));
#762=DIRECTION('',(0.,0.,1.));
#763=DIRECTION('',(1.,0.,0.));
#764=AXIS2_PLACEMENT_3D('',#761,#762,#763);
#765=PLANE('',#764);
#766=ORIENTED_EDGE('',*,*,#133,.F.);
#767=EDGE_LOOP('',(#766));
#768=FACE_BOUND('',#767,.T.);
#769=ORIENTED_EDGE('',*,*,#159,.F.);
#770=EDGE_LOOP('',(#769));
#771=FACE_BOUND('',#770,.T.);
#772=ORIENTED_EDGE('',*,*,#191,.F.);
#773=EDGE_LOOP('',(#772));
#774=FACE_BOUND('',#773,.T.);
#775=ORIENTED_EDGE('',*,*,#224,.F.);
#776=EDGE_LOOP('',(#775));
#777=FACE_BOUND('',#776,.T.);
#778=ORIENTED_EDGE('',*,*,#257,.F.);
#779=EDGE_LOOP('',(#778));
#780=FACE_BOUND('',#779,.T.);
#781=ORIENTED_EDGE('',*,*,#283,.F.);
#782=EDGE_LOOP('',(#781));
#783=FACE_BOUND('',#782,.T.);
#784=ORIENTED_EDGE('',*,*,#315,.F.);
#785=EDGE_LOOP('',(#784));
#786=FACE_BOUND('',#785,.T.);
#787=ORIENTED_EDGE('',*,*,#348,.F.);
#788=EDGE_LOOP('',(#787));
#789=FACE_BOUND('',#788,.T.);
#790=ORIENTED_EDGE('',*,*,#374,.F.);
#791=EDGE_LOOP('',(#790));
#792=FACE_BOUND('',#791,.T.);
#793=ORIENTED_EDGE('',*,*,#406,.F.);
#794=EDGE_LOOP('',(#793));
#795=FACE_BOUND('',#794,.T.);
#796=ORIENTED_EDGE('',*,*,#439,.F.);
#797=EDGE_LOOP('',(#796));
#798=FACE_BOUND('',#797,.T.);
#799=CARTESIAN_POINT('',(0.,0.,44.));
#800=DIRECTION('',(0.,0.,1.));
#801=DIRECTION('',(1.,0.,0.));
#802=AXIS2_PLACEMENT_3D('',#799,#800,#801);
#803=CIRCLE('',#802,62.);
#804=CARTESIAN_POINT('',(62.,0.,44.));
#805=VERTEX_POINT('',#804);
#806=EDGE_CURVE('E459',#805,#805,#803,.T.);
#807=ORIENTED_EDGE('',*,*,#806,.T.);
#808=EDGE_LOOP('',(#807));
#809=FACE_BOUND('',#808,.T.);
#810=ADVANCED_FACE('F437',(#768,#771,#774,#777,#780,#783,#786,#789,#792,#795,#798,#809),#765,.T.);
#811=CARTESIAN_POINT('',(18.212485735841,59.264705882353,38.));
#812=CARTESIAN_POINT('',(14.678563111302,60.35070663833,38.));
#813=CARTESIAN_POINT('',(11.072687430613,61.202567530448,37.713108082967));
#814=CARTESIAN_POINT('',(7.412310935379,61.814925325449,37.381306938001));
#815=CARTESIAN_POINT('',(3.715342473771,62.183903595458,37.100373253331));
#816=CARTESIAN_POINT('',(7.593925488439E-13,62.307157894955,36.924679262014));
#817=CARTESIAN_POINT('',(-3.715342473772,62.183903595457,37.100373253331));
#818=CARTESIAN_POINT('',(-7.412310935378,61.814925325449,37.381306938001));
#819=CARTESIAN_POINT('',(-11.07268743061,61.202567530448,37.713108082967));
#820=CARTESIAN_POINT('',(-14.6785631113,60.35070663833,38.));
#821=CARTESIAN_POINT('',(-18.21248573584,59.264705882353,38.));
#822=CARTESIAN_POINT('',(18.212485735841,59.264705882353,32.));
#823=CARTESIAN_POINT('',(15.011002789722,60.248545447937,33.128852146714));
#824=CARTESIAN_POINT('',(11.408617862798,61.1365528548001,33.61290290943));
#825=CARTESIAN_POINT('',(7.690166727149,61.781787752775,33.764650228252));
#826=CARTESIAN_POINT('',(3.855528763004,62.191216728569,33.781440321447));
#827=CARTESIAN_POINT('',(2.46881233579E-13,62.315841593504,33.713484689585));
#828=CARTESIAN_POINT('',(-3.855528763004,62.191216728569,33.781440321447));
#829=CARTESIAN_POINT('',(-7.69016672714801,61.7817877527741,33.764650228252));
#830=CARTESIAN_POINT('',(-11.40861786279,61.1365528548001,33.61290290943));
#831=CARTESIAN_POINT('',(-15.01100278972,60.248545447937,33.128852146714));
#832=CARTESIAN_POINT('',(-18.21248573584,59.264705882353,32.));
#833=CARTESIAN_POINT('',(19.974984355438,65.,32.));
#834=CARTESIAN_POINT('',(15.733036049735,65.,32.));
#835=CARTESIAN_POINT('',(11.663825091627,65.,32.));
#836=CARTESIAN_POINT('',(7.713585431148,65.,32.));
#837=CARTESIAN_POINT('',(3.838562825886,65.,31.999999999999));
#838=CARTESIAN_POINT('',(-7.585043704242E-13,64.999999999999,32.000000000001));
#839=CARTESIAN_POINT('',(-3.838562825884,65.,31.999999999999));
#840=CARTESIAN_POINT('',(-7.713585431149,65.,32.));
#841=CARTESIAN_POINT('',(-11.66382509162,65.,32.));
#842=CARTESIAN_POINT('',(-15.73303604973,65.,32.));
#843=CARTESIAN_POINT('',(-19.97498435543,65.,32.));
#844=(BOUNDED_SURFACE() B_SPLINE_SURFACE(2,10,((#811,#812,#813,#814,#815,#816,#817,#818,#819,
#820,#821),(#822,#823,#824,#825,#826,#827,#828,#829,#830,#831,#832),(#833,#834,#835,#836,#837,
#838,#839,#840,#841,#842,#843)),.UNSPECIFIED.,.F.,.F.,.F.) B_SPLINE_SURFACE_WITH_KNOTS((3,3),
(11,11),(0.,36.970267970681),(78.904238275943,115.87450624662),
.UNSPECIFIED.) GEOMETRIC_REPRESENTATION_ITEM() RATIONAL_B_SPLINE_SURFACE(((1.,1.,1.,1.,1.,1.,1.,
1.,1.,1.,1.),(0.707106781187,0.780532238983,0.826675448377,0.858068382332,0.874709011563,
0.88123116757,0.874709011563,0.858068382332,0.826675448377,0.780532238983,0.707106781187),(1.,
1.,1.,1.,1.,1.,1.,1.,1.,1.,1.))) REPRESENTATION_ITEM('') SURFACE());
#845=CARTESIAN_POINT('',(19.974984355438,65.,38.));
#846=DIRECTION('',(-0.955882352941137,0.293749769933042,0.));
#847=DIRECTION('',(0.293749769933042,0.955882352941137,0.));
#848=AXIS2_PLACEMENT_3D('',#845,#846,#847);
#849=CIRCLE('',#848,6.);
#850=CARTESIAN_POINT('',(19.974984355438,65.,32.));
#851=VERTEX_POINT('',#850);
#852=CARTESIAN_POINT('',(18.212485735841,59.264705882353,38.));
#853=VERTEX_POINT('',#852);
#854=EDGE_CURVE('E640',#851,#853,#849,.T.);
#855=CARTESIAN_POINT('',(19.974984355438,65.,32.));
#856=CARTESIAN_POINT('',(15.733036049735,65.,32.));
#857=CARTESIAN_POINT('',(11.663825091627,65.,32.));
#858=CARTESIAN_POINT('',(7.713585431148,65.,32.));
#859=CARTESIAN_POINT('',(3.838562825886,65.,31.999999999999));
#860=CARTESIAN_POINT('',(-7.585043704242E-13,64.999999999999,32.000000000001));
#861=CARTESIAN_POINT('',(-3.838562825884,65.,31.999999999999));
#862=CARTESIAN_POINT('',(-7.713585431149,65.,32.));
#863=CARTESIAN_POINT('',(-11.66382509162,65.,32.));
#864=CARTESIAN_POINT('',(-15.73303604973,65.,32.));
#865=CARTESIAN_POINT('',(-19.97498435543,65.,32.));
#866=(BOUNDED_CURVE() B_SPLINE_CURVE(10,(#855,#856,#857,#858,#859,#860,#861,#862,#863,#864,
#865),.UNSPECIFIED.,.F.,.F.) B_SPLINE_CURVE_WITH_KNOTS((11,11),(78.904238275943,
115.87450624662),
.UNSPECIFIED.) CURVE() GEOMETRIC_REPRESENTATION_ITEM() RATIONAL_B_SPLINE_CURVE((1.,1.,1.,1.,1.,
1.,1.,1.,1.,1.,1.)) REPRESENTATION_ITEM(''));
#867=CARTESIAN_POINT('',(-19.97498435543,65.,32.));
#868=VERTEX_POINT('',#867);
#869=EDGE_CURVE('E584',#851,#868,#866,.T.);
#870=CARTESIAN_POINT('',(-19.97498435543,65.,32.));
#871=CARTESIAN_POINT('',(-18.21248573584,59.264705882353,32.));
#872=CARTESIAN_POINT('',(-18.21248573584,59.264705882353,38.));
#873=(BOUNDED_CURVE() B_SPLINE_CURVE(2,(#870,#871,#872),.UNSPECIFIED.,.F.,
.F.) B_SPLINE_CURVE_WITH_KNOTS((3,3),(0.,36.970267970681),
.UNSPECIFIED.) CURVE() GEOMETRIC_REPRESENTATION_ITEM() RATIONAL_B_SPLINE_CURVE((1.,
0.707106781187,1.)) REPRESENTATION_ITEM(''));
#874=CARTESIAN_POINT('',(-18.21248573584,59.264705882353,38.));
#875=VERTEX_POINT('',#874);
#876=EDGE_CURVE('E591',#868,#875,#873,.T.);
#877=CARTESIAN_POINT('',(18.212485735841,59.264705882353,38.));
#878=CARTESIAN_POINT('',(14.678563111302,60.35070663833,38.));
#879=CARTESIAN_POINT('',(11.072687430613,61.202567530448,37.713108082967));
#880=CARTESIAN_POINT('',(7.412310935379,61.814925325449,37.381306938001));
#881=CARTESIAN_POINT('',(3.715342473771,62.183903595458,37.100373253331));
#882=CARTESIAN_POINT('',(7.593925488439E-13,62.307157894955,36.924679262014));
#883=CARTESIAN_POINT('',(-3.715342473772,62.183903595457,37.100373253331));
#884=CARTESIAN_POINT('',(-7.412310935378,61.814925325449,37.381306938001));
#885=CARTESIAN_POINT('',(-11.07268743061,61.202567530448,37.713108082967));
#886=CARTESIAN_POINT('',(-14.6785631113,60.35070663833,38.));
#887=CARTESIAN_POINT('',(-18.21248573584,59.264705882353,38.));
#888=(BOUNDED_CURVE() B_SPLINE_CURVE(10,(#877,#878,#879,#880,#881,#882,#883,#884,#885,#886,
#887),.UNSPECIFIED.,.F.,.F.) B_SPLINE_CURVE_WITH_KNOTS((11,11),(78.904238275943,
115.87450624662),
.UNSPECIFIED.) CURVE() GEOMETRIC_REPRESENTATION_ITEM() RATIONAL_B_SPLINE_CURVE((1.,1.,1.,1.,1.,
1.,1.,1.,1.,1.,1.)) REPRESENTATION_ITEM(''));
#889=EDGE_CURVE('E471',#853,#875,#888,.T.);
#890=ORIENTED_EDGE('',*,*,#854,.F.);
#891=ORIENTED_EDGE('',*,*,#869,.T.);
#892=ORIENTED_EDGE('',*,*,#876,.T.);
#893=ORIENTED_EDGE('',*,*,#889,.F.);
#894=EDGE_LOOP('',(#890,#891,#892,#893));
#895=FACE_BOUND('',#894,.T.);
#896=ADVANCED_FACE('F442',(#895),#844,.T.);
#897=CARTESIAN_POINT('',(35.355339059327,35.355339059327,-0.1));
#898=DIRECTION('',(0.,0.,1.));
#899=DIRECTION('',(1.,0.,0.));
#900=AXIS2_PLACEMENT_3D('',#897,#898,#899);
#901=CYLINDRICAL_SURFACE('',#900,5.5);
#902=CARTESIAN_POINT('',(35.355339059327,35.355339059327,0.));
#903=DIRECTION('',(0.,0.,1.));
#904=DIRECTION('',(1.,0.,0.));
#905=AXIS2_PLACEMENT_3D('',#902,#903,#904);
#906=CIRCLE('',#905,5.5);
#907=CARTESIAN_POINT('',(40.855339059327,35.355339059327,0.));
#908=VERTEX_POINT('',#907);
#909=EDGE_CURVE('E563',#908,#908,#906,.T.);
#910=ORIENTED_EDGE('',*,*,#909,.F.);
#911=DIRECTION('',(0.,0.,1.));
#912=VECTOR('',#911,1.);
#913=CARTESIAN_POINT('',(40.855339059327,35.355339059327,-0.1));
#914=LINE('',#913,#912);
#915=EDGE_CURVE('E282',#908,#459,#914,.T.);
#916=ORIENTED_EDGE('',*,*,#915,.T.);
#917=ORIENTED_EDGE('',*,*,#460,.T.);
#918=ORIENTED_EDGE('',*,*,#915,.F.);
#919=EDGE_LOOP('',(#910,#916,#917,#918));
#920=FACE_BOUND('',#919,.T.);
#921=ADVANCED_FACE('F961',(#920),#901,.F.);
#922=CARTESIAN_POINT('',(0.,50.,-0.1));
#923=DIRECTION('',(0.,0.,1.));
#924=DIRECTION('',(1.,0.,0.));
#925=AXIS2_PLACEMENT_3D('',#922,#923,#924);
#926=CYLINDRICAL_SURFACE('',#925,5.5);
#927=CARTESIAN_POINT('',(0.,50.,0.));
#928=DIRECTION('',(0.,0.,1.));
#929=DIRECTION('',(1.,0.,0.));
#930=AXIS2_PLACEMENT_3D('',#927,#928,#929);
#931=CIRCLE('',#930,5.5);
#932=CARTESIAN_POINT('',(5.5,50.,0.));
#933=VERTEX_POINT('',#932);
#934=EDGE_CURVE('E597',#933,#933,#931,.T.);
#935=ORIENTED_EDGE('',*,*,#934,.F.);
#936=DIRECTION('',(0.,0.,1.));
#937=VECTOR('',#936,1.);
#938=CARTESIAN_POINT('',(5.5,50.,-0.1));
#939=LINE('',#938,#937);
#940=EDGE_CURVE('E284',#933,#479,#939,.T.);
#941=ORIENTED_EDGE('',*,*,#940,.T.);
#942=ORIENTED_EDGE('',*,*,#480,.T.);
#943=ORIENTED_EDGE('',*,*,#940,.F.);
#944=EDGE_LOOP('',(#935,#941,#942,#943));
#945=FACE_BOUND('',#944,.T.);
#946=ADVANCED_FACE('F980',(#945),#926,.F.);
#947=CARTESIAN_POINT('',(16.838071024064,40.650699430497,0.));
#948=DIRECTION('',(0.,0.,1.));
#949=DIRECTION('',(1.,0.,0.));
#950=AXIS2_PLACEMENT_3D('',#947,#948,#949);
#951=CYLINDRICAL_SURFACE('',#950,1.65);
#952=DIRECTION('',(0.,0.,1.));
#953=VECTOR('',#952,1.);
#954=CARTESIAN_POINT('',(18.488071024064,40.650699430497,0.));
#955=LINE('',#954,#953);
#956=CARTESIAN_POINT('',(18.488071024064,40.650699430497,0.));
#957=VERTEX_POINT('',#956);
#958=EDGE_CURVE('E283',#957,#496,#955,.T.);
#959=ORIENTED_EDGE('',*,*,#958,.F.);
#960=CARTESIAN_POINT('',(16.838071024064,40.650699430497,0.));
#961=DIRECTION('',(0.,0.,1.));
#962=DIRECTION('',(1.,0.,0.));
#963=AXIS2_PLACEMENT_3D('',#960,#961,#962);
#964=CIRCLE('',#963,1.65);
#965=EDGE_CURVE('E598',#957,#957,#964,.T.);
#966=ORIENTED_EDGE('',*,*,#965,.F.);
#967=ORIENTED_EDGE('',*,*,#958,.T.);
#968=ORIENTED_EDGE('',*,*,#497,.T.);
#969=EDGE_LOOP('',(#959,#966,#967,#968));
#970=FACE_BOUND('',#969,.T.);
#971=ADVANCED_FACE('F977',(#970),#951,.F.);
#972=CARTESIAN_POINT('',(40.650699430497,16.838071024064,0.));
#973=DIRECTION('',(0.,0.,1.));
#974=DIRECTION('',(1.,0.,0.));
#975=AXIS2_PLACEMENT_3D('',#972,#973,#974);
#976=CYLINDRICAL_SURFACE('',#975,1.65);
#977=DIRECTION('',(0.,0.,1.));
#978=VECTOR('',#977,1.);
#979=CARTESIAN_POINT('',(42.300699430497,16.838071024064,0.));
#980=LINE('',#979,#978);
#981=CARTESIAN_POINT('',(42.300699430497,16.838071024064,0.));
#982=VERTEX_POINT('',#981);
#983=EDGE_CURVE('E546',#982,#513,#980,.T.);
#984=ORIENTED_EDGE('',*,*,#983,.F.);
#985=CARTESIAN_POINT('',(40.650699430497,16.838071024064,0.));
#986=DIRECTION('',(0.,0.,1.));
#987=DIRECTION('',(1.,0.,0.));
#988=AXIS2_PLACEMENT_3D('',#985,#986,#987);
#989=CIRCLE('',#988,1.65);
#990=EDGE_CURVE('E582',#982,#982,#989,.T.);
#991=ORIENTED_EDGE('',*,*,#990,.F.);
#992=ORIENTED_EDGE('',*,*,#983,.T.);
#993=ORIENTED_EDGE('',*,*,#514,.T.);
#994=EDGE_LOOP('',(#984,#991,#992,#993));
#995=FACE_BOUND('',#994,.T.);
#996=ADVANCED_FACE('F985',(#995),#976,.F.);
#997=CARTESIAN_POINT('',(50.,0.,-0.1));
#998=DIRECTION('',(0.,0.,1.));
#999=DIRECTION('',(1.,0.,0.));
#1000=AXIS2_PLACEMENT_3D('',#997,#998,#999);
#1001=CYLINDRICAL_SURFACE('',#1000,5.5);
#1002=CARTESIAN_POINT('',(50.,0.,0.));
#1003=DIRECTION('',(0.,0.,1.));
#1004=DIRECTION('',(1.,0.,0.));
#1005=AXIS2_PLACEMENT_3D('',#1002,#1003,#1004);
#1006=CIRCLE('',#1005,5.5);
#1007=CARTESIAN_POINT('',(55.5,0.,0.));
#1008=VERTEX_POINT('',#1007);
#1009=EDGE_CURVE('E579',#1008,#1008,#1006,.T.);
#1010=ORIENTED_EDGE('',*,*,#1009,.F.);
#1011=DIRECTION('',(0.,0.,1.));
#1012=VECTOR('',#1011,1.);
#1013=CARTESIAN_POINT('',(55.5,0.,-0.1));
#1014=LINE('',#1013,#1012);
#1015=EDGE_CURVE('E275',#1008,#533,#1014,.T.);
#1016=ORIENTED_EDGE('',*,*,#1015,.T.);
#1017=ORIENTED_EDGE('',*,*,#534,.T.);
#1018=ORIENTED_EDGE('',*,*,#1015,.F.);
#1019=EDGE_LOOP('',(#1010,#1016,#1017,#1018));
#1020=FACE_BOUND('',#1019,.T.);
#1021=ADVANCED_FACE('F986',(#1020),#1001,.F.);
#1022=CARTESIAN_POINT('',(0.,0.,0.));
#1023=DIRECTION('',(0.,0.,1.));
#1024=DIRECTION('',(1.,0.,0.));
#1025=AXIS2_PLACEMENT_3D('',#1022,#1023,#1024);
#1026=CYLINDRICAL_SURFACE('',#1025,39.1);
#1027=DIRECTION('',(0.,0.,1.));
#1028=VECTOR('',#1027,1.);
#1029=CARTESIAN_POINT('',(39.1,0.,0.));
#1030=LINE('',#1029,#1028);
#1031=CARTESIAN_POINT('',(39.1,0.,0.));
#1032=VERTEX_POINT('',#1031);
#1033=EDGE_CURVE('E266',#1032,#553,#1030,.T.);
#1034=ORIENTED_EDGE('',*,*,#1033,.F.);
#1035=CARTESIAN_POINT('',(0.,0.,0.));
#1036=DIRECTION('',(0.,0.,1.));
#1037=DIRECTION('',(1.,0.,0.));
#1038=AXIS2_PLACEMENT_3D('',#1035,#1036,#1037);
#1039=CIRCLE('',#1038,39.1);
#1040=EDGE_CURVE('E573',#1032,#1032,#1039,.T.);
#1041=ORIENTED_EDGE('',*,*,#1040,.F.);
#1042=ORIENTED_EDGE('',*,*,#1033,.T.);
#1043=ORIENTED_EDGE('',*,*,#554,.T.);
#1044=EDGE_LOOP('',(#1034,#1041,#1042,#1043));
#1045=FACE_BOUND('',#1044,.T.);
#1046=ADVANCED_FACE('F989',(#1045),#1026,.F.);
#1047=CARTESIAN_POINT('',(-16.83807102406,40.650699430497,0.));
#1048=DIRECTION('',(0.,0.,1.));
#1049=DIRECTION('',(1.,0.,0.));
#1050=AXIS2_PLACEMENT_3D('',#1047,#1048,#1049);
#1051=CYLINDRICAL_SURFACE('',#1050,1.65);
#1052=DIRECTION('',(0.,0.,1.));
#1053=VECTOR('',#1052,1.);
#1054=CARTESIAN_POINT('',(-15.18807102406,40.650699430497,0.));
#1055=LINE('',#1054,#1053);
#1056=CARTESIAN_POINT('',(-15.18807102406,40.650699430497,0.));
#1057=VERTEX_POINT('',#1056);
#1058=EDGE_CURVE('E255',#1057,#570,#1055,.T.);
#1059=ORIENTED_EDGE('',*,*,#1058,.F.);
#1060=CARTESIAN_POINT('',(-16.83807102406,40.650699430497,0.));
#1061=DIRECTION('',(0.,0.,1.));
#1062=DIRECTION('',(1.,0.,0.));
#1063=AXIS2_PLACEMENT_3D('',#1060,#1061,#1062);
#1064=CIRCLE('',#1063,1.65);
#1065=EDGE_CURVE('E566',#1057,#1057,#1064,.T.);
#1066=ORIENTED_EDGE('',*,*,#1065,.F.);
#1067=ORIENTED_EDGE('',*,*,#1058,.T.);
#1068=ORIENTED_EDGE('',*,*,#571,.T.);
#1069=EDGE_LOOP('',(#1059,#1066,#1067,#1068));
#1070=FACE_BOUND('',#1069,.T.);
#1071=ADVANCED_FACE('F995',(#1070),#1051,.F.);
#1072=CARTESIAN_POINT('',(-35.35533905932,35.355339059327,-0.1));
#1073=DIRECTION('',(0.,0.,1.));
#1074=DIRECTION('',(1.,0.,0.));
#1075=AXIS2_PLACEMENT_3D('',#1072,#1073,#1074);
#1076=CYLINDRICAL_SURFACE('',#1075,5.5);
#1077=CARTESIAN_POINT('',(-35.35533905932,35.355339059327,0.));
#1078=DIRECTION('',(0.,0.,1.));
#1079=DIRECTION('',(1.,0.,0.));
#1080=AXIS2_PLACEMENT_3D('',#1077,#1078,#1079);
#1081=CIRCLE('',#1080,5.5);
#1082=CARTESIAN_POINT('',(-29.85533905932,35.355339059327,0.));
#1083=VERTEX_POINT('',#1082);
#1084=EDGE_CURVE('E507',#1083,#1083,#1081,.T.);
#1085=ORIENTED_EDGE('',*,*,#1084,.F.);
#1086=DIRECTION('',(0.,0.,1.));
#1087=VECTOR('',#1086,1.);
#1088=CARTESIAN_POINT('',(-29.85533905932,35.355339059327,-0.1));
#1089=LINE('',#1088,#1087);
#1090=EDGE_CURVE('E248',#1083,#590,#1089,.T.);
#1091=ORIENTED_EDGE('',*,*,#1090,.T.);
#1092=ORIENTED_EDGE('',*,*,#591,.T.);
#1093=ORIENTED_EDGE('',*,*,#1090,.F.);
#1094=EDGE_LOOP('',(#1085,#1091,#1092,#1093));
#1095=FACE_BOUND('',#1094,.T.);
#1096=ADVANCED_FACE('F249',(#1095),#1076,.F.);
#1097=CARTESIAN_POINT('',(-40.65069943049,16.838071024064,0.));
#1098=DIRECTION('',(0.,0.,1.));
#1099=DIRECTION('',(1.,0.,0.));
#1100=AXIS2_PLACEMENT_3D('',#1097,#1098,#1099);
#1101=CYLINDRICAL_SURFACE('',#1100,1.65);
#1102=DIRECTION('',(0.,0.,1.));
#1103=VECTOR('',#1102,1.);
#1104=CARTESIAN_POINT('',(-39.00069943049,16.838071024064,0.));
#1105=LINE('',#1104,#1103);
#1106=CARTESIAN_POINT('',(-39.00069943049,16.838071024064,0.));
#1107=VERTEX_POINT('',#1106);
#1108=EDGE_CURVE('E387',#1107,#607,#1105,.T.);
#1109=ORIENTED_EDGE('',*,*,#1108,.F.);
#1110=CARTESIAN_POINT('',(-40.65069943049,16.838071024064,0.));
#1111=DIRECTION('',(0.,0.,1.));
#1112=DIRECTION('',(1.,0.,0.));
#1113=AXIS2_PLACEMENT_3D('',#1110,#1111,#1112);
#1114=CIRCLE('',#1113,1.65);
#1115=EDGE_CURVE('E513',#1107,#1107,#1114,.T.);
#1116=ORIENTED_EDGE('',*,*,#1115,.F.);
#1117=ORIENTED_EDGE('',*,*,#1108,.T.);
#1118=ORIENTED_EDGE('',*,*,#608,.T.);
#1119=EDGE_LOOP('',(#1109,#1116,#1117,#1118));
#1120=FACE_BOUND('',#1119,.T.);
#1121=ADVANCED_FACE('F999',(#1120),#1101,.F.);
#1122=CARTESIAN_POINT('',(-50.,0.,-0.1));
#1123=DIRECTION('',(0.,0.,1.));
#1124=DIRECTION('',(1.,0.,0.));
#1125=AXIS2_PLACEMENT_3D('',#1122,#1123,#1124);
#1126=CYLINDRICAL_SURFACE('',#1125,5.5);
#1127=CARTESIAN_POINT('',(-50.,0.,0.));
#1128=DIRECTION('',(0.,0.,1.));
#1129=DIRECTION('',(1.,0.,0.));
#1130=AXIS2_PLACEMENT_3D('',#1127,#1128,#1129);
#1131=CIRCLE('',#1130,5.5);
#1132=CARTESIAN_POINT('',(-44.5,0.,0.));
#1133=VERTEX_POINT('',#1132);
#1134=EDGE_CURVE('E543',#1133,#1133,#1131,.T.);
#1135=ORIENTED_EDGE('',*,*,#1134,.F.);
#1136=DIRECTION('',(0.,0.,1.));
#1137=VECTOR('',#1136,1.);
#1138=CARTESIAN_POINT('',(-44.5,0.,-0.1));
#1139=LINE('',#1138,#1137);
#1140=EDGE_CURVE('E393',#1133,#627,#1139,.T.);
#1141=ORIENTED_EDGE('',*,*,#1140,.T.);
#1142=ORIENTED_EDGE('',*,*,#628,.T.);
#1143=ORIENTED_EDGE('',*,*,#1140,.F.);
#1144=EDGE_LOOP('',(#1135,#1141,#1142,#1143));
#1145=FACE_BOUND('',#1144,.T.);
#1146=ADVANCED_FACE('F1001',(#1145),#1126,.F.);
#1147=CARTESIAN_POINT('',(40.650699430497,-16.83807102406,0.));
#1148=DIRECTION('',(0.,0.,1.));
#1149=DIRECTION('',(1.,0.,0.));
#1150=AXIS2_PLACEMENT_3D('',#1147,#1148,#1149);
#1151=CYLINDRICAL_SURFACE('',#1150,1.65);
#1152=DIRECTION('',(0.,0.,1.));
#1153=VECTOR('',#1152,1.);
#1154=CARTESIAN_POINT('',(42.300699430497,-16.83807102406,0.));
#1155=LINE('',#1154,#1153);
#1156=CARTESIAN_POINT('',(42.300699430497,-16.83807102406,0.));
#1157=VERTEX_POINT('',#1156);
#1158=EDGE_CURVE('E421',#1157,#644,#1155,.T.);
#1159=ORIENTED_EDGE('',*,*,#1158,.F.);
#1160=CARTESIAN_POINT('',(40.650699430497,-16.83807102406,0.));
#1161=DIRECTION('',(0.,0.,1.));
#1162=DIRECTION('',(1.,0.,0.));
#1163=AXIS2_PLACEMENT_3D('',#1160,#1161,#1162);
#1164=CIRCLE('',#1163,1.65);
#1165=EDGE_CURVE('E537',#1157,#1157,#1164,.T.);
#1166=ORIENTED_EDGE('',*,*,#1165,.F.);
#1167=ORIENTED_EDGE('',*,*,#1158,.T.);
#1168=ORIENTED_EDGE('',*,*,#645,.T.);
#1169=EDGE_LOOP('',(#1159,#1166,#1167,#1168));
#1170=FACE_BOUND('',#1169,.T.);
#1171=ADVANCED_FACE('F1002',(#1170),#1151,.F.);
#1172=CARTESIAN_POINT('',(35.355339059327,-35.35533905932,-0.1));
#1173=DIRECTION('',(0.,0.,1.));
#1174=DIRECTION('',(1.,0.,0.));
#1175=AXIS2_PLACEMENT_3D('',#1172,#1173,#1174);
#1176=CYLINDRICAL_SURFACE('',#1175,5.5);
#1177=CARTESIAN_POINT('',(35.355339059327,-35.35533905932,0.));
#1178=DIRECTION('',(0.,0.,1.));
#1179=DIRECTION('',(1.,0.,0.));
#1180=AXIS2_PLACEMENT_3D('',#1177,#1178,#1179);
#1181=CIRCLE('',#1180,5.5);
#1182=CARTESIAN_POINT('',(40.855339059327,-35.35533905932,0.));
#1183=VERTEX_POINT('',#1182);
#1184=EDGE_CURVE('E531',#1183,#1183,#1181,.T.);
#1185=ORIENTED_EDGE('',*,*,#1184,.F.);
#1186=DIRECTION('',(0.,0.,1.));
#1187=VECTOR('',#1186,1.);
#1188=CARTESIAN_POINT('',(40.855339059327,-35.35533905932,-0.1));
#1189=LINE('',#1188,#1187);
#1190=EDGE_CURVE('E414',#1183,#664,#1189,.T.);
#1191=ORIENTED_EDGE('',*,*,#1190,.T.);
#1192=ORIENTED_EDGE('',*,*,#665,.T.);
#1193=ORIENTED_EDGE('',*,*,#1190,.F.);
#1194=EDGE_LOOP('',(#1185,#1191,#1192,#1193));
#1195=FACE_BOUND('',#1194,.T.);
#1196=ADVANCED_FACE('F1006',(#1195),#1176,.F.);
#1197=CARTESIAN_POINT('',(16.838071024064,-40.65069943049,0.));
#1198=DIRECTION('',(0.,0.,1.));
#1199=DIRECTION('',(1.,0.,0.));
#1200=AXIS2_PLACEMENT_3D('',#1197,#1198,#1199);
#1201=CYLINDRICAL_SURFACE('',#1200,1.65);
#1202=DIRECTION('',(0.,0.,1.));
#1203=VECTOR('',#1202,1.);
#1204=CARTESIAN_POINT('',(18.488071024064,-40.65069943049,0.));
#1205=LINE('',#1204,#1203);
#1206=CARTESIAN_POINT('',(18.488071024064,-40.65069943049,0.));
#1207=VERTEX_POINT('',#1206);
#1208=EDGE_CURVE('E402',#1207,#681,#1205,.T.);
#1209=ORIENTED_EDGE('',*,*,#1208,.F.);
#1210=CARTESIAN_POINT('',(16.838071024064,-40.65069943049,0.));
#1211=DIRECTION('',(0.,0.,1.));
#1212=DIRECTION('',(1.,0.,0.));
#1213=AXIS2_PLACEMENT_3D('',#1210,#1211,#1212);
#1214=CIRCLE('',#1213,1.65);
#1215=EDGE_CURVE('E524',#1207,#1207,#1214,.T.);
#1216=ORIENTED_EDGE('',*,*,#1215,.F.);
#1217=ORIENTED_EDGE('',*,*,#1208,.T.);
#1218=ORIENTED_EDGE('',*,*,#682,.T.);
#1219=EDGE_LOOP('',(#1209,#1216,#1217,#1218));
#1220=FACE_BOUND('',#1219,.T.);
#1221=ADVANCED_FACE('F1009',(#1220),#1201,.F.);
#1222=CARTESIAN_POINT('',(-40.65069943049,-16.83807102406,0.));
#1223=DIRECTION('',(0.,0.,1.));
#1224=DIRECTION('',(1.,0.,0.));
#1225=AXIS2_PLACEMENT_3D('',#1222,#1223,#1224);
#1226=CYLINDRICAL_SURFACE('',#1225,1.65);
#1227=DIRECTION('',(0.,0.,1.));
#1228=VECTOR('',#1227,1.);
#1229=CARTESIAN_POINT('',(-39.00069943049,-16.83807102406,0.));
#1230=LINE('',#1229,#1228);
#1231=CARTESIAN_POINT('',(-39.00069943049,-16.83807102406,0.));
#1232=VERTEX_POINT('',#1231);
#1233=EDGE_CURVE('E759',#1232,#698,#1230,.T.);
#1234=ORIENTED_EDGE('',*,*,#1233,.F.);
#1235=CARTESIAN_POINT('',(-40.65069943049,-16.83807102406,0.));
#1236=DIRECTION('',(0.,0.,1.));
#1237=DIRECTION('',(1.,0.,0.));
#1238=AXIS2_PLACEMENT_3D('',#1235,#1236,#1237);
#1239=CIRCLE('',#1238,1.65);
#1240=EDGE_CURVE('E517',#1232,#1232,#1239,.T.);
#1241=ORIENTED_EDGE('',*,*,#1240,.F.);
#1242=ORIENTED_EDGE('',*,*,#1233,.T.);
#1243=ORIENTED_EDGE('',*,*,#699,.T.);
#1244=EDGE_LOOP('',(#1234,#1241,#1242,#1243));
#1245=FACE_BOUND('',#1244,.T.);
#1246=ADVANCED_FACE('F1014',(#1245),#1226,.F.);
#1247=CARTESIAN_POINT('',(-16.83807102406,-40.65069943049,0.));
#1248=DIRECTION('',(0.,0.,1.));
#1249=DIRECTION('',(1.,0.,0.));
#1250=AXIS2_PLACEMENT_3D('',#1247,#1248,#1249);
#1251=CYLINDRICAL_SURFACE('',#1250,1.65);
#1252=DIRECTION('',(0.,0.,1.));
#1253=VECTOR('',#1252,1.);
#1254=CARTESIAN_POINT('',(-15.18807102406,-40.65069943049,0.));
#1255=LINE('',#1254,#1253);
#1256=CARTESIAN_POINT('',(-15.18807102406,-40.65069943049,0.));
#1257=VERTEX_POINT('',#1256);
#1258=EDGE_CURVE('E397',#1257,#715,#1255,.T.);
#1259=ORIENTED_EDGE('',*,*,#1258,.F.);
#1260=CARTESIAN_POINT('',(-16.83807102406,-40.65069943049,0.));
#1261=DIRECTION('',(0.,0.,1.));
#1262=DIRECTION('',(1.,0.,0.));
#1263=AXIS2_PLACEMENT_3D('',#1260,#1261,#1262);
#1264=CIRCLE('',#1263,1.65);
#1265=EDGE_CURVE('E512',#1257,#1257,#1264,.T.);
#1266=ORIENTED_EDGE('',*,*,#1265,.F.);
#1267=ORIENTED_EDGE('',*,*,#1258,.T.);
#1268=ORIENTED_EDGE('',*,*,#716,.T.);
#1269=EDGE_LOOP('',(#1259,#1266,#1267,#1268));
#1270=FACE_BOUND('',#1269,.T.);
#1271=ADVANCED_FACE('F849',(#1270),#1251,.F.);
#1272=CARTESIAN_POINT('',(0.,-50.,-0.1));
#1273=DIRECTION('',(0.,0.,1.));
#1274=DIRECTION('',(1.,0.,0.));
#1275=AXIS2_PLACEMENT_3D('',#1272,#1273,#1274);
#1276=CYLINDRICAL_SURFACE('',#1275,5.5);
#1277=CARTESIAN_POINT('',(0.,-50.,0.));
#1278=DIRECTION('',(0.,0.,1.));
#1279=DIRECTION('',(1.,0.,0.));
#1280=AXIS2_PLACEMENT_3D('',#1277,#1278,#1279);
#1281=CIRCLE('',#1280,5.5);
#1282=CARTESIAN_POINT('',(5.5,-50.,0.));
#1283=VERTEX_POINT('',#1282);
#1284=EDGE_CURVE('E518',#1283,#1283,#1281,.T.);
#1285=ORIENTED_EDGE('',*,*,#1284,.F.);
#1286=DIRECTION('',(0.,0.,1.));
#1287=VECTOR('',#1286,1.);
#1288=CARTESIAN_POINT('',(5.5,-50.,-0.1));
#1289=LINE('',#1288,#1287);
#1290=EDGE_CURVE('E386',#1283,#735,#1289,.T.);
#1291=ORIENTED_EDGE('',*,*,#1290,.T.);
#1292=ORIENTED_EDGE('',*,*,#736,.T.);
#1293=ORIENTED_EDGE('',*,*,#1290,.F.);
#1294=EDGE_LOOP('',(#1285,#1291,#1292,#1293));
#1295=FACE_BOUND('',#1294,.T.);
#1296=ADVANCED_FACE('F1186',(#1295),#1276,.F.);
#1297=CARTESIAN_POINT('',(-35.35533905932,-35.35533905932,-0.1));
#1298=DIRECTION('',(0.,0.,1.));
#1299=DIRECTION('',(1.,0.,0.));
#1300=AXIS2_PLACEMENT_3D('',#1297,#1298,#1299);
#1301=CYLINDRICAL_SURFACE('',#1300,5.5);
#1302=CARTESIAN_POINT('',(-35.35533905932,-35.35533905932,0.));
#1303=DIRECTION('',(0.,0.,1.));
#1304=DIRECTION('',(1.,0.,0.));
#1305=AXIS2_PLACEMENT_3D('',#1302,#1303,#1304);
#1306=CIRCLE('',#1305,5.5);
#1307=CARTESIAN_POINT('',(-29.85533905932,-35.35533905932,0.));
#1308=VERTEX_POINT('',#1307);
#1309=EDGE_CURVE('E506',#1308,#1308,#1306,.T.);
#1310=ORIENTED_EDGE('',*,*,#1309,.F.);
#1311=DIRECTION('',(0.,0.,1.));
#1312=VECTOR('',#1311,1.);
#1313=CARTESIAN_POINT('',(-29.85533905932,-35.35533905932,-0.1));
#1314=LINE('',#1313,#1312);
#1315=EDGE_CURVE('E652',#1308,#755,#1314,.T.);
#1316=ORIENTED_EDGE('',*,*,#1315,.T.);
#1317=ORIENTED_EDGE('',*,*,#756,.T.);
#1318=ORIENTED_EDGE('',*,*,#1315,.F.);
#1319=EDGE_LOOP('',(#1310,#1316,#1317,#1318));
#1320=FACE_BOUND('',#1319,.T.);
#1321=ADVANCED_FACE('F1171',(#1320),#1301,.F.);
#1322=CARTESIAN_POINT('',(65.,50.,-0.1));
#1323=DIRECTION('',(0.,0.,1.));
#1324=DIRECTION('',(1.,0.,0.));
#1325=AXIS2_PLACEMENT_3D('',#1322,#1323,#1324);
#1326=CYLINDRICAL_SURFACE('',#1325,4.5);
#1327=DIRECTION('',(0.,0.,1.));
#1328=VECTOR('',#1327,1.);
#1329=CARTESIAN_POINT('',(69.5,50.,-0.1));
#1330=LINE('',#1329,#1328);
#1331=CARTESIAN_POINT('',(69.5,50.,0.));
#1332=VERTEX_POINT('',#1331);
#1333=CARTESIAN_POINT('',(69.5,50.,32.));
#1334=VERTEX_POINT('',#1333);
#1335=EDGE_CURVE('E647',#1332,#1334,#1330,.T.);
#1336=ORIENTED_EDGE('',*,*,#1335,.F.);
#1337=CARTESIAN_POINT('',(65.,50.,0.));
#1338=DIRECTION('',(0.,0.,1.));
#1339=DIRECTION('',(1.,0.,0.));
#1340=AXIS2_PLACEMENT_3D('',#1337,#1338,#1339);
#1341=CIRCLE('',#1340,4.5);
#1342=EDGE_CURVE('E559',#1332,#1332,#1341,.T.);
#1343=ORIENTED_EDGE('',*,*,#1342,.F.);
#1344=ORIENTED_EDGE('',*,*,#1335,.T.);
#1345=CARTESIAN_POINT('',(65.,50.,32.));
#1346=DIRECTION('',(0.,0.,1.));
#1347=DIRECTION('',(1.,0.,0.));
#1348=AXIS2_PLACEMENT_3D('',#1345,#1346,#1347);
#1349=CIRCLE('',#1348,4.5);
#1350=EDGE_CURVE('E491',#1334,#1334,#1349,.T.);
#1351=ORIENTED_EDGE('',*,*,#1350,.T.);
#1352=EDGE_LOOP('',(#1336,#1343,#1344,#1351));
#1353=FACE_BOUND('',#1352,.T.);
#1354=ADVANCED_FACE('F1188',(#1353),#1326,.F.);
#1355=CARTESIAN_POINT('',(65.,-50.,-0.1));
#1356=DIRECTION('',(0.,0.,1.));
#1357=DIRECTION('',(1.,0.,0.));
#1358=AXIS2_PLACEMENT_3D('',#1355,#1356,#1357);
#1359=CYLINDRICAL_SURFACE('',#1358,4.5);
#1360=DIRECTION('',(0.,0.,1.));
#1361=VECTOR('',#1360,1.);
#1362=CARTESIAN_POINT('',(69.5,-50.,-0.1));
#1363=LINE('',#1362,#1361);
#1364=CARTESIAN_POINT('',(69.5,-50.,0.));
#1365=VERTEX_POINT('',#1364);
#1366=CARTESIAN_POINT('',(69.5,-50.,32.));
#1367=VERTEX_POINT('',#1366);
#1368=EDGE_CURVE('E642',#1365,#1367,#1363,.T.);
#1369=ORIENTED_EDGE('',*,*,#1368,.F.);
#1370=CARTESIAN_POINT('',(65.,-50.,0.));
#1371=DIRECTION('',(0.,0.,1.));
#1372=DIRECTION('',(1.,0.,0.));
#1373=AXIS2_PLACEMENT_3D('',#1370,#1371,#1372);
#1374=CIRCLE('',#1373,4.5);
#1375=EDGE_CURVE('E530',#1365,#1365,#1374,.T.);
#1376=ORIENTED_EDGE('',*,*,#1375,.F.);
#1377=ORIENTED_EDGE('',*,*,#1368,.T.);
#1378=CARTESIAN_POINT('',(65.,-50.,32.));
#1379=DIRECTION('',(0.,0.,1.));
#1380=DIRECTION('',(1.,0.,0.));
#1381=AXIS2_PLACEMENT_3D('',#1378,#1379,#1380);
#1382=CIRCLE('',#1381,4.5);
#1383=EDGE_CURVE('E484',#1367,#1367,#1382,.T.);
#1384=ORIENTED_EDGE('',*,*,#1383,.T.);
#1385=EDGE_LOOP('',(#1369,#1376,#1377,#1384));
#1386=FACE_BOUND('',#1385,.T.);
#1387=ADVANCED_FACE('F1184',(#1386),#1359,.F.);
#1388=CARTESIAN_POINT('',(0.,0.,38.));
#1389=DIRECTION('',(0.,0.,-1.));
#1390=DIRECTION('',(1.,0.,0.));
#1391=AXIS2_PLACEMENT_3D('',#1388,#1389,#1390);
#1392=TOROIDAL_SURFACE('',#1391,68.,6.);
#1393=CARTESIAN_POINT('',(19.974984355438,-65.,32.));
#1394=CARTESIAN_POINT('',(18.212485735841,-59.26470588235,32.));
#1395=CARTESIAN_POINT('',(18.212485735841,-59.26470588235,38.));
#1396=(BOUNDED_CURVE() B_SPLINE_CURVE(2,(#1393,#1394,#1395),.UNSPECIFIED.,.F.,
.F.) B_SPLINE_CURVE_WITH_KNOTS((3,3),(0.,36.970267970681),
.UNSPECIFIED.) CURVE() GEOMETRIC_REPRESENTATION_ITEM() RATIONAL_B_SPLINE_CURVE((1.,
0.707106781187,1.)) REPRESENTATION_ITEM(''));
#1397=CARTESIAN_POINT('',(19.974984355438,-65.,32.));
#1398=VERTEX_POINT('',#1397);
#1399=CARTESIAN_POINT('',(18.212485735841,-59.26470588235,38.));
#1400=VERTEX_POINT('',#1399);
#1401=EDGE_CURVE('E671',#1398,#1400,#1396,.T.);
#1402=ORIENTED_EDGE('',*,*,#1401,.F.);
#1403=CARTESIAN_POINT('',(0.,0.,32.));
#1404=DIRECTION('',(0.,0.,-1.));
#1405=DIRECTION('',(0.293749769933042,0.955882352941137,0.));
#1406=AXIS2_PLACEMENT_3D('',#1403,#1404,#1405);
#1407=CIRCLE('',#1406,68.);
#1408=EDGE_CURVE('E486',#851,#1398,#1407,.T.);
#1409=ORIENTED_EDGE('',*,*,#1408,.F.);
#1410=ORIENTED_EDGE('',*,*,#854,.T.);
#1411=CARTESIAN_POINT('',(0.,0.,38.));
#1412=DIRECTION('',(0.,0.,1.));
#1413=DIRECTION('',(1.,0.,0.));
#1414=AXIS2_PLACEMENT_3D('',#1411,#1412,#1413);
#1415=CIRCLE('',#1414,62.);
#1416=CARTESIAN_POINT('',(62.,0.,38.));
#1417=VERTEX_POINT('',#1416);
#1418=EDGE_CURVE('E464',#1417,#853,#1415,.T.);
#1419=ORIENTED_EDGE('',*,*,#1418,.F.);
#1420=CARTESIAN_POINT('',(0.,0.,38.));
#1421=DIRECTION('',(0.,0.,1.));
#1422=DIRECTION('',(1.,0.,0.));
#1423=AXIS2_PLACEMENT_3D('',#1420,#1421,#1422);
#1424=CIRCLE('',#1423,62.);
#1425=EDGE_CURVE('E477',#1400,#1417,#1424,.T.);
#1426=ORIENTED_EDGE('',*,*,#1425,.F.);
#1427=EDGE_LOOP('',(#1402,#1409,#1410,#1419,#1426));
#1428=FACE_BOUND('',#1427,.T.);
#1429=ADVANCED_FACE('F713',(#1428),#1392,.F.);
#1430=CARTESIAN_POINT('',(0.,0.,32.));
#1431=DIRECTION('',(0.,0.,1.));
#1432=DIRECTION('',(1.,0.,0.));
#1433=AXIS2_PLACEMENT_3D('',#1430,#1431,#1432);
#1434=CYLINDRICAL_SURFACE('',#1433,62.);
#1435=DIRECTION('',(0.,0.,1.));
#1436=VECTOR('',#1435,1.);
#1437=CARTESIAN_POINT('',(62.,0.,32.));
#1438=LINE('',#1437,#1436);
#1439=EDGE_CURVE('E467',#1417,#805,#1438,.T.);
#1440=ORIENTED_EDGE('',*,*,#1439,.T.);
#1441=ORIENTED_EDGE('',*,*,#806,.F.);
#1442=ORIENTED_EDGE('',*,*,#1439,.F.);
#1443=ORIENTED_EDGE('',*,*,#1418,.T.);
#1444=ORIENTED_EDGE('',*,*,#889,.T.);
#1445=CARTESIAN_POINT('',(0.,0.,38.));
#1446=DIRECTION('',(0.,0.,1.));
#1447=DIRECTION('',(1.,0.,0.));
#1448=AXIS2_PLACEMENT_3D('',#1445,#1446,#1447);
#1449=CIRCLE('',#1448,62.);
#1450=CARTESIAN_POINT('',(-18.21248573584,-59.26470588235,38.));
#1451=VERTEX_POINT('',#1450);
#1452=EDGE_CURVE('E618',#875,#1451,#1449,.T.);
#1453=ORIENTED_EDGE('',*,*,#1452,.T.);
#1454=CARTESIAN_POINT('',(-18.21248573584,-59.26470588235,38.));
#1455=CARTESIAN_POINT('',(-14.6785631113,-60.35070663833,38.));
#1456=CARTESIAN_POINT('',(-11.07268743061,-61.20256753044,37.713108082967));
#1457=CARTESIAN_POINT('',(-7.412310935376,-61.81492532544,37.381306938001));
#1458=CARTESIAN_POINT('',(-3.715342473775,-62.18390359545,37.100373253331));
#1459=CARTESIAN_POINT('',(4.011013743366E-12,-62.30715789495,36.924679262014));
#1460=CARTESIAN_POINT('',(3.715342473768,-62.18390359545,37.100373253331));
#1461=CARTESIAN_POINT('',(7.41231093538,-61.81492532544,37.381306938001));
#1462=CARTESIAN_POINT('',(11.072687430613,-61.20256753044,37.713108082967));
#1463=CARTESIAN_POINT('',(14.678563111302,-60.35070663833,38.));
#1464=CARTESIAN_POINT('',(18.212485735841,-59.26470588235,38.));
#1465=(BOUNDED_CURVE() B_SPLINE_CURVE(10,(#1454,#1455,#1456,#1457,#1458,#1459,#1460,#1461,#1462,
#1463,#1464),.UNSPECIFIED.,.F.,.F.) B_SPLINE_CURVE_WITH_KNOTS((11,11),(273.68298279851,
310.65325076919),
.UNSPECIFIED.) CURVE() GEOMETRIC_REPRESENTATION_ITEM() RATIONAL_B_SPLINE_CURVE((1.,1.,1.,1.,1.,
1.,1.,1.,1.,1.,1.)) REPRESENTATION_ITEM(''));
#1466=EDGE_CURVE('E689',#1451,#1400,#1465,.T.);
#1467=ORIENTED_EDGE('',*,*,#1466,.T.);
#1468=ORIENTED_EDGE('',*,*,#1425,.T.);
#1469=EDGE_LOOP('',(#1440,#1441,#1442,#1443,#1444,#1453,#1467,#1468));
#1470=FACE_BOUND('',#1469,.T.);
#1471=ADVANCED_FACE('F798',(#1470),#1434,.T.);
#1472=CARTESIAN_POINT('',(-65.,50.,-0.1));
#1473=DIRECTION('',(0.,0.,1.));
#1474=DIRECTION('',(1.,0.,0.));
#1475=AXIS2_PLACEMENT_3D('',#1472,#1473,#1474);
#1476=CYLINDRICAL_SURFACE('',#1475,4.5);
#1477=DIRECTION('',(0.,0.,1.));
#1478=VECTOR('',#1477,1.);
#1479=CARTESIAN_POINT('',(-60.5,50.,-0.1));
#1480=LINE('',#1479,#1478);
#1481=CARTESIAN_POINT('',(-60.5,50.,0.));
#1482=VERTEX_POINT('',#1481);
#1483=CARTESIAN_POINT('',(-60.5,50.,32.));
#1484=VERTEX_POINT('',#1483);
#1485=EDGE_CURVE('E478',#1482,#1484,#1480,.T.);
#1486=ORIENTED_EDGE('',*,*,#1485,.F.);
#1487=CARTESIAN_POINT('',(-65.,50.,0.));
#1488=DIRECTION('',(0.,0.,1.));
#1489=DIRECTION('',(1.,0.,0.));
#1490=AXIS2_PLACEMENT_3D('',#1487,#1488,#1489);
#1491=CIRCLE('',#1490,4.5);
#1492=EDGE_CURVE('E511',#1482,#1482,#1491,.T.);
#1493=ORIENTED_EDGE('',*,*,#1492,.F.);
#1494=ORIENTED_EDGE('',*,*,#1485,.T.);
#1495=CARTESIAN_POINT('',(-65.,50.,32.));
#1496=DIRECTION('',(0.,0.,1.));
#1497=DIRECTION('',(1.,0.,0.));
#1498=AXIS2_PLACEMENT_3D('',#1495,#1496,#1497);
#1499=CIRCLE('',#1498,4.5);
#1500=EDGE_CURVE('E674',#1484,#1484,#1499,.T.);
#1501=ORIENTED_EDGE('',*,*,#1500,.T.);
#1502=EDGE_LOOP('',(#1486,#1493,#1494,#1501));
#1503=FACE_BOUND('',#1502,.T.);
#1504=ADVANCED_FACE('F1152',(#1503),#1476,.F.);
#1505=CARTESIAN_POINT('',(-65.,-50.,-0.1));
#1506=DIRECTION('',(0.,0.,1.));
#1507=DIRECTION('',(1.,0.,0.));
#1508=AXIS2_PLACEMENT_3D('',#1505,#1506,#1507);
#1509=CYLINDRICAL_SURFACE('',#1508,4.5);
#1510=DIRECTION('',(0.,0.,1.));
#1511=VECTOR('',#1510,1.);
#1512=CARTESIAN_POINT('',(-60.5,-50.,-0.1));
#1513=LINE('',#1512,#1511);
#1514=CARTESIAN_POINT('',(-60.5,-50.,0.));
#1515=VERTEX_POINT('',#1514);
#1516=CARTESIAN_POINT('',(-60.5,-50.,32.));
#1517=VERTEX_POINT('',#1516);
#1518=EDGE_CURVE('E627',#1515,#1517,#1513,.T.);
#1519=ORIENTED_EDGE('',*,*,#1518,.F.);
#1520=CARTESIAN_POINT('',(-65.,-50.,0.));
#1521=DIRECTION('',(0.,0.,1.));
#1522=DIRECTION('',(1.,0.,0.));
#1523=AXIS2_PLACEMENT_3D('',#1520,#1521,#1522);
#1524=CIRCLE('',#1523,4.5);
#1525=EDGE_CURVE('E498',#1515,#1515,#1524,.T.);
#1526=ORIENTED_EDGE('',*,*,#1525,.F.);
#1527=ORIENTED_EDGE('',*,*,#1518,.T.);
#1528=CARTESIAN_POINT('',(-65.,-50.,32.));
#1529=DIRECTION('',(0.,0.,1.));
#1530=DIRECTION('',(1.,0.,0.));
#1531=AXIS2_PLACEMENT_3D('',#1528,#1529,#1530);
#1532=CIRCLE('',#1531,4.5);
#1533=EDGE_CURVE('E677',#1517,#1517,#1532,.T.);
#1534=ORIENTED_EDGE('',*,*,#1533,.T.);
#1535=EDGE_LOOP('',(#1519,#1526,#1527,#1534));
#1536=FACE_BOUND('',#1535,.T.);
#1537=ADVANCED_FACE('F1161',(#1536),#1509,.F.);
#1538=CARTESIAN_POINT('',(0.,0.,38.));
#1539=DIRECTION('',(0.,0.,-1.));
#1540=DIRECTION('',(1.,0.,0.));
#1541=AXIS2_PLACEMENT_3D('',#1538,#1539,#1540);
#1542=TOROIDAL_SURFACE('',#1541,68.,6.);
#1543=ORIENTED_EDGE('',*,*,#876,.F.);
#1544=CARTESIAN_POINT('',(0.,0.,32.));
#1545=DIRECTION('',(0.,0.,1.));
#1546=DIRECTION('',(1.,0.,0.));
#1547=AXIS2_PLACEMENT_3D('',#1544,#1545,#1546);
#1548=CIRCLE('',#1547,68.);
#1549=CARTESIAN_POINT('',(-19.97498435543,-65.,32.));
#1550=VERTEX_POINT('',#1549);
#1551=EDGE_CURVE('E783',#868,#1550,#1548,.T.);
#1552=ORIENTED_EDGE('',*,*,#1551,.T.);
#1553=CARTESIAN_POINT('',(-19.97498435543,-65.,38.));
#1554=DIRECTION('',(0.955882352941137,-0.293749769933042,0.));
#1555=DIRECTION('',(-0.293749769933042,-0.955882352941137,0.));
#1556=AXIS2_PLACEMENT_3D('',#1553,#1554,#1555);
#1557=CIRCLE('',#1556,6.);
#1558=EDGE_CURVE('E678',#1550,#1451,#1557,.T.);
#1559=ORIENTED_EDGE('',*,*,#1558,.T.);
#1560=ORIENTED_EDGE('',*,*,#1452,.F.);
#1561=EDGE_LOOP('',(#1543,#1552,#1559,#1560));
#1562=FACE_BOUND('',#1561,.T.);
#1563=ADVANCED_FACE('F811',(#1562),#1542,.F.);
#1564=CARTESIAN_POINT('',(-80.,65.,0.));
#1565=DIRECTION('',(0.,1.,0.));
#1566=DIRECTION('',(1.,0.,0.));
#1567=AXIS2_PLACEMENT_3D('',#1564,#1565,#1566);
#1568=PLANE('',#1567);
#1569=DIRECTION('',(1.,0.,0.));
#1570=VECTOR('',#1569,1.);
#1571=CARTESIAN_POINT('',(-80.,65.,32.));
#1572=LINE('',#1571,#1570);
#1573=CARTESIAN_POINT('',(-80.,65.,32.));
#1574=VERTEX_POINT('',#1573);
#1575=EDGE_CURVE('E774',#1574,#868,#1572,.T.);
#1576=ORIENTED_EDGE('',*,*,#1575,.T.);
#1577=ORIENTED_EDGE('',*,*,#869,.F.);
#1578=DIRECTION('',(1.,0.,0.));
#1579=VECTOR('',#1578,1.);
#1580=CARTESIAN_POINT('',(-80.,65.,32.));
#1581=LINE('',#1580,#1579);
#1582=CARTESIAN_POINT('',(80.,65.,32.));
#1583=VERTEX_POINT('',#1582);
#1584=EDGE_CURVE('E686',#851,#1583,#1581,.T.);
#1585=ORIENTED_EDGE('',*,*,#1584,.T.);
#1586=DIRECTION('',(0.,0.,1.));
#1587=VECTOR('',#1586,1.);
#1588=CARTESIAN_POINT('',(80.,65.,0.));
#1589=LINE('',#1588,#1587);
#1590=CARTESIAN_POINT('',(80.,65.,0.));
#1591=VERTEX_POINT('',#1590);
#1592=EDGE_CURVE('E565',#1591,#1583,#1589,.T.);
#1593=ORIENTED_EDGE('',*,*,#1592,.F.);
#1594=DIRECTION('',(1.,0.,0.));
#1595=VECTOR('',#1594,1.);
#1596=CARTESIAN_POINT('',(-80.,65.,0.));
#1597=LINE('',#1596,#1595);
#1598=CARTESIAN_POINT('',(-80.,65.,0.));
#1599=VERTEX_POINT('',#1598);
#1600=EDGE_CURVE('E490',#1599,#1591,#1597,.T.);
#1601=ORIENTED_EDGE('',*,*,#1600,.F.);
#1602=DIRECTION('',(0.,0.,1.));
#1603=VECTOR('',#1602,1.);
#1604=CARTESIAN_POINT('',(-80.,65.,0.));
#1605=LINE('',#1604,#1603);
#1606=EDGE_CURVE('E682',#1599,#1574,#1605,.T.);
#1607=ORIENTED_EDGE('',*,*,#1606,.T.);
#1608=EDGE_LOOP('',(#1576,#1577,#1585,#1593,#1601,#1607));
#1609=FACE_BOUND('',#1608,.T.);
#1610=ADVANCED_FACE('F1056',(#1609),#1568,.T.);
#1611=CARTESIAN_POINT('',(80.,-65.,0.));
#1612=DIRECTION('',(1.,0.,0.));
#1613=DIRECTION('',(0.,1.,0.));
#1614=AXIS2_PLACEMENT_3D('',#1611,#1612,#1613);
#1615=PLANE('',#1614);
#1616=DIRECTION('',(0.,0.,1.));
#1617=VECTOR('',#1616,1.);
#1618=CARTESIAN_POINT('',(80.,-65.,0.));
#1619=LINE('',#1618,#1617);
#1620=CARTESIAN_POINT('',(80.,-65.,0.));
#1621=VERTEX_POINT('',#1620);
#1622=CARTESIAN_POINT('',(80.,-65.,32.));
#1623=VERTEX_POINT('',#1622);
#1624=EDGE_CURVE('E732',#1621,#1623,#1619,.T.);
#1625=ORIENTED_EDGE('',*,*,#1624,.F.);
#1626=DIRECTION('',(0.,1.,0.));
#1627=VECTOR('',#1626,1.);
#1628=CARTESIAN_POINT('',(80.,-65.,0.));
#1629=LINE('',#1628,#1627);
#1630=EDGE_CURVE('E489',#1621,#1591,#1629,.T.);
#1631=ORIENTED_EDGE('',*,*,#1630,.T.);
#1632=ORIENTED_EDGE('',*,*,#1592,.T.);
#1633=DIRECTION('',(0.,1.,0.));
#1634=VECTOR('',#1633,1.);
#1635=CARTESIAN_POINT('',(80.,-65.,32.));
#1636=LINE('',#1635,#1634);
#1637=EDGE_CURVE('E485',#1623,#1583,#1636,.T.);
#1638=ORIENTED_EDGE('',*,*,#1637,.F.);
#1639=EDGE_LOOP('',(#1625,#1631,#1632,#1638));
#1640=FACE_BOUND('',#1639,.T.);
#1641=ADVANCED_FACE('F1029',(#1640),#1615,.T.);
#1642=CARTESIAN_POINT('',(-80.,-65.,0.));
#1643=DIRECTION('',(0.,0.,1.));
#1644=DIRECTION('',(1.,0.,0.));
#1645=AXIS2_PLACEMENT_3D('',#1642,#1643,#1644);
#1646=PLANE('',#1645);
#1647=ORIENTED_EDGE('',*,*,#1342,.T.);
#1648=EDGE_LOOP('',(#1647));
#1649=FACE_BOUND('',#1648,.T.);
#1650=ORIENTED_EDGE('',*,*,#909,.T.);
#1651=EDGE_LOOP('',(#1650));
#1652=FACE_BOUND('',#1651,.T.);
#1653=ORIENTED_EDGE('',*,*,#934,.T.);
#1654=EDGE_LOOP('',(#1653));
#1655=FACE_BOUND('',#1654,.T.);
#1656=ORIENTED_EDGE('',*,*,#965,.T.);
#1657=EDGE_LOOP('',(#1656));
#1658=FACE_BOUND('',#1657,.T.);
#1659=ORIENTED_EDGE('',*,*,#990,.T.);
#1660=EDGE_LOOP('',(#1659));
#1661=FACE_BOUND('',#1660,.T.);
#1662=ORIENTED_EDGE('',*,*,#1009,.T.);
#1663=EDGE_LOOP('',(#1662));
#1664=FACE_BOUND('',#1663,.T.);
#1665=ORIENTED_EDGE('',*,*,#1040,.T.);
#1666=EDGE_LOOP('',(#1665));
#1667=FACE_BOUND('',#1666,.T.);
#1668=ORIENTED_EDGE('',*,*,#1065,.T.);
#1669=EDGE_LOOP('',(#1668));
#1670=FACE_BOUND('',#1669,.T.);
#1671=ORIENTED_EDGE('',*,*,#1492,.T.);
#1672=EDGE_LOOP('',(#1671));
#1673=FACE_BOUND('',#1672,.T.);
#1674=ORIENTED_EDGE('',*,*,#1084,.T.);
#1675=EDGE_LOOP('',(#1674));
#1676=FACE_BOUND('',#1675,.T.);
#1677=ORIENTED_EDGE('',*,*,#1115,.T.);
#1678=EDGE_LOOP('',(#1677));
#1679=FACE_BOUND('',#1678,.T.);
#1680=ORIENTED_EDGE('',*,*,#1134,.T.);
#1681=EDGE_LOOP('',(#1680));
#1682=FACE_BOUND('',#1681,.T.);
#1683=ORIENTED_EDGE('',*,*,#1165,.T.);
#1684=EDGE_LOOP('',(#1683));
#1685=FACE_BOUND('',#1684,.T.);
#1686=ORIENTED_EDGE('',*,*,#1184,.T.);
#1687=EDGE_LOOP('',(#1686));
#1688=FACE_BOUND('',#1687,.T.);
#1689=ORIENTED_EDGE('',*,*,#1375,.T.);
#1690=EDGE_LOOP('',(#1689));
#1691=FACE_BOUND('',#1690,.T.);
#1692=ORIENTED_EDGE('',*,*,#1215,.T.);
#1693=EDGE_LOOP('',(#1692));
#1694=FACE_BOUND('',#1693,.T.);
#1695=ORIENTED_EDGE('',*,*,#1240,.T.);
#1696=EDGE_LOOP('',(#1695));
#1697=FACE_BOUND('',#1696,.T.);
#1698=ORIENTED_EDGE('',*,*,#1265,.T.);
#1699=EDGE_LOOP('',(#1698));
#1700=FACE_BOUND('',#1699,.T.);
#1701=ORIENTED_EDGE('',*,*,#1284,.T.);
#1702=EDGE_LOOP('',(#1701));
#1703=FACE_BOUND('',#1702,.T.);
#1704=ORIENTED_EDGE('',*,*,#1309,.T.);
#1705=EDGE_LOOP('',(#1704));
#1706=FACE_BOUND('',#1705,.T.);
#1707=ORIENTED_EDGE('',*,*,#1525,.T.);
#1708=EDGE_LOOP('',(#1707));
#1709=FACE_BOUND('',#1708,.T.);
#1710=ORIENTED_EDGE('',*,*,#1600,.T.);
#1711=ORIENTED_EDGE('',*,*,#1630,.F.);
#1712=DIRECTION('',(1.,0.,0.));
#1713=VECTOR('',#1712,1.);
#1714=CARTESIAN_POINT('',(-80.,-65.,0.));
#1715=LINE('',#1714,#1713);
#1716=CARTESIAN_POINT('',(-80.,-65.,0.));
#1717=VERTEX_POINT('',#1716);
#1718=EDGE_CURVE('E742',#1717,#1621,#1715,.T.);
#1719=ORIENTED_EDGE('',*,*,#1718,.F.);
#1720=DIRECTION('',(0.,1.,0.));
#1721=VECTOR('',#1720,1.);
#1722=CARTESIAN_POINT('',(-80.,-65.,0.));
#1723=LINE('',#1722,#1721);
#1724=EDGE_CURVE('E690',#1717,#1599,#1723,.T.);
#1725=ORIENTED_EDGE('',*,*,#1724,.T.);
#1726=EDGE_LOOP('',(#1710,#1711,#1719,#1725));
#1727=FACE_BOUND('',#1726,.T.);
#1728=ADVANCED_FACE('F1028',(#1649,#1652,#1655,#1658,#1661,#1664,#1667,#1670,#1673,#1676,#1679,
#1682,#1685,#1688,#1691,#1694,#1697,#1700,#1703,#1706,#1709,#1727),#1646,.F.);
#1729=CARTESIAN_POINT('',(-80.,-65.,32.));
#1730=DIRECTION('',(0.,0.,1.));
#1731=DIRECTION('',(1.,0.,0.));
#1732=AXIS2_PLACEMENT_3D('',#1729,#1730,#1731);
#1733=PLANE('',#1732);
#1734=ORIENTED_EDGE('',*,*,#1350,.F.);
#1735=EDGE_LOOP('',(#1734));
#1736=FACE_BOUND('',#1735,.T.);
#1737=ORIENTED_EDGE('',*,*,#1383,.F.);
#1738=EDGE_LOOP('',(#1737));
#1739=FACE_BOUND('',#1738,.T.);
#1740=ORIENTED_EDGE('',*,*,#1584,.F.);
#1741=ORIENTED_EDGE('',*,*,#1408,.T.);
#1742=DIRECTION('',(1.,0.,0.));
#1743=VECTOR('',#1742,1.);
#1744=CARTESIAN_POINT('',(-80.,-65.,32.));
#1745=LINE('',#1744,#1743);
#1746=EDGE_CURVE('E702',#1398,#1623,#1745,.T.);
#1747=ORIENTED_EDGE('',*,*,#1746,.T.);
#1748=ORIENTED_EDGE('',*,*,#1637,.T.);
#1749=EDGE_LOOP('',(#1740,#1741,#1747,#1748));
#1750=FACE_BOUND('',#1749,.T.);
#1751=ADVANCED_FACE('F701',(#1736,#1739,#1750),#1733,.T.);
#1752=CARTESIAN_POINT('',(-80.,-65.,0.));
#1753=DIRECTION('',(1.,0.,0.));
#1754=DIRECTION('',(0.,1.,0.));
#1755=AXIS2_PLACEMENT_3D('',#1752,#1753,#1754);
#1756=PLANE('',#1755);
#1757=DIRECTION('',(0.,1.,0.));
#1758=VECTOR('',#1757,1.);
#1759=CARTESIAN_POINT('',(-80.,-65.,32.));
#1760=LINE('',#1759,#1758);
#1761=CARTESIAN_POINT('',(-80.,-65.,32.));
#1762=VERTEX_POINT('',#1761);
#1763=EDGE_CURVE('E777',#1762,#1574,#1760,.T.);
#1764=ORIENTED_EDGE('',*,*,#1763,.T.);
#1765=ORIENTED_EDGE('',*,*,#1606,.F.);
#1766=ORIENTED_EDGE('',*,*,#1724,.F.);
#1767=DIRECTION('',(0.,0.,1.));
#1768=VECTOR('',#1767,1.);
#1769=CARTESIAN_POINT('',(-80.,-65.,0.));
#1770=LINE('',#1769,#1768);
#1771=EDGE_CURVE('E824',#1717,#1762,#1770,.T.);
#1772=ORIENTED_EDGE('',*,*,#1771,.T.);
#1773=EDGE_LOOP('',(#1764,#1765,#1766,#1772));
#1774=FACE_BOUND('',#1773,.T.);
#1775=ADVANCED_FACE('F831',(#1774),#1756,.F.);
#1776=CARTESIAN_POINT('',(-18.21248573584,-59.26470588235,38.));
#1777=CARTESIAN_POINT('',(-14.6785631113,-60.35070663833,38.));
#1778=CARTESIAN_POINT('',(-11.07268743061,-61.20256753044,37.713108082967));
#1779=CARTESIAN_POINT('',(-7.412310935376,-61.81492532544,37.381306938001));
#1780=CARTESIAN_POINT('',(-3.715342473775,-62.18390359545,37.100373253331));
#1781=CARTESIAN_POINT('',(4.011013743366E-12,-62.30715789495,36.924679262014));
#1782=CARTESIAN_POINT('',(3.715342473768,-62.18390359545,37.100373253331));
#1783=CARTESIAN_POINT('',(7.41231093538,-61.81492532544,37.381306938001));
#1784=CARTESIAN_POINT('',(11.072687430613,-61.20256753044,37.713108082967));
#1785=CARTESIAN_POINT('',(14.678563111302,-60.35070663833,38.));
#1786=CARTESIAN_POINT('',(18.212485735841,-59.26470588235,38.));
#1787=CARTESIAN_POINT('',(-18.21248573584,-59.26470588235,32.));
#1788=CARTESIAN_POINT('',(-15.01100278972,-60.2485454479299,33.128852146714));
#1789=CARTESIAN_POINT('',(-11.4086178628,-61.1365528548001,33.61290290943));
#1790=CARTESIAN_POINT('',(-7.690166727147,-61.78178775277,33.764650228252));
#1791=CARTESIAN_POINT('',(-3.855528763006,-62.19121672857,33.781440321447));
#1792=CARTESIAN_POINT('',(1.79199035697E-12,-62.3158415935,33.713484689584));
#1793=CARTESIAN_POINT('',(3.855528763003,-62.19121672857,33.781440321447));
#1794=CARTESIAN_POINT('',(7.690166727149,-61.78178775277,33.764650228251));
#1795=CARTESIAN_POINT('',(11.408617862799,-61.1365528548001,33.61290290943));
#1796=CARTESIAN_POINT('',(15.011002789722,-60.2485454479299,33.128852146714));
#1797=CARTESIAN_POINT('',(18.212485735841,-59.26470588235,32.));
#1798=CARTESIAN_POINT('',(-19.97498435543,-65.,32.));
#1799=CARTESIAN_POINT('',(-15.73303604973,-65.,32.));
#1800=CARTESIAN_POINT('',(-11.66382509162,-65.,32.));
#1801=CARTESIAN_POINT('',(-7.713585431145,-65.,32.));
#1802=CARTESIAN_POINT('',(-3.83856282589,-65.,32.));
#1803=CARTESIAN_POINT('',(5.575984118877E-12,-65.,32.));
#1804=CARTESIAN_POINT('',(3.838562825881,-65.,32.));
#1805=CARTESIAN_POINT('',(7.71358543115,-65.,32.));
#1806=CARTESIAN_POINT('',(11.663825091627,-65.,32.));
#1807=CARTESIAN_POINT('',(15.733036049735,-65.,32.));
#1808=CARTESIAN_POINT('',(19.974984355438,-65.,32.));
#1809=(BOUNDED_SURFACE() B_SPLINE_SURFACE(2,10,((#1776,#1777,#1778,#1779,#1780,#1781,#1782,
#1783,#1784,#1785,#1786),(#1787,#1788,#1789,#1790,#1791,#1792,#1793,#1794,#1795,#1796,#1797),
(#1798,#1799,#1800,#1801,#1802,#1803,#1804,#1805,#1806,#1807,#1808)),.UNSPECIFIED.,.F.,.F.,
.F.) B_SPLINE_SURFACE_WITH_KNOTS((3,3),(11,11),(0.,36.970267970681),(273.68298279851,
310.65325076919),.UNSPECIFIED.) GEOMETRIC_REPRESENTATION_ITEM() RATIONAL_B_SPLINE_SURFACE(((1.,
1.,1.,1.,1.,1.,1.,1.,1.,1.,1.),(0.707106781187,0.780532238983,0.826675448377,0.858068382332,
0.874709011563,0.88123116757,0.874709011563,0.858068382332,0.826675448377,0.780532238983,
0.707106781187),(1.,1.,1.,1.,1.,1.,1.,1.,1.,1.,1.))) REPRESENTATION_ITEM('') SURFACE());
#1810=CARTESIAN_POINT('',(-19.97498435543,-65.,32.));
#1811=CARTESIAN_POINT('',(-15.73303604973,-65.,32.));
#1812=CARTESIAN_POINT('',(-11.66382509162,-65.,32.));
#1813=CARTESIAN_POINT('',(-7.713585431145,-65.,32.));
#1814=CARTESIAN_POINT('',(-3.83856282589,-65.,32.));
#1815=CARTESIAN_POINT('',(5.575984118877E-12,-65.,32.));
#1816=CARTESIAN_POINT('',(3.838562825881,-65.,32.));
#1817=CARTESIAN_POINT('',(7.71358543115,-65.,32.));
#1818=CARTESIAN_POINT('',(11.663825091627,-65.,32.));
#1819=CARTESIAN_POINT('',(15.733036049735,-65.,32.));
#1820=CARTESIAN_POINT('',(19.974984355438,-65.,32.));
#1821=(BOUNDED_CURVE() B_SPLINE_CURVE(10,(#1810,#1811,#1812,#1813,#1814,#1815,#1816,#1817,#1818,
#1819,#1820),.UNSPECIFIED.,.F.,.F.) B_SPLINE_CURVE_WITH_KNOTS((11,11),(273.68298279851,
310.65325076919),
.UNSPECIFIED.) CURVE() GEOMETRIC_REPRESENTATION_ITEM() RATIONAL_B_SPLINE_CURVE((1.,1.,1.,1.,1.,
1.,1.,1.,1.,1.,1.)) REPRESENTATION_ITEM(''));
#1822=EDGE_CURVE('E722',#1550,#1398,#1821,.T.);
#1823=ORIENTED_EDGE('',*,*,#1558,.F.);
#1824=ORIENTED_EDGE('',*,*,#1822,.T.);
#1825=ORIENTED_EDGE('',*,*,#1401,.T.);
#1826=ORIENTED_EDGE('',*,*,#1466,.F.);
#1827=EDGE_LOOP('',(#1823,#1824,#1825,#1826));
#1828=FACE_BOUND('',#1827,.T.);
#1829=ADVANCED_FACE('F724',(#1828),#1809,.T.);
#1830=CARTESIAN_POINT('',(-80.,-65.,32.));
#1831=DIRECTION('',(0.,0.,1.));
#1832=DIRECTION('',(1.,0.,0.));
#1833=AXIS2_PLACEMENT_3D('',#1830,#1831,#1832);
#1834=PLANE('',#1833);
#1835=ORIENTED_EDGE('',*,*,#1500,.F.);
#1836=EDGE_LOOP('',(#1835));
#1837=FACE_BOUND('',#1836,.T.);
#1838=ORIENTED_EDGE('',*,*,#1533,.F.);
#1839=EDGE_LOOP('',(#1838));
#1840=FACE_BOUND('',#1839,.T.);
#1841=ORIENTED_EDGE('',*,*,#1575,.F.);
#1842=ORIENTED_EDGE('',*,*,#1763,.F.);
#1843=DIRECTION('',(1.,0.,0.));
#1844=VECTOR('',#1843,1.);
#1845=CARTESIAN_POINT('',(-80.,-65.,32.));
#1846=LINE('',#1845,#1844);
#1847=EDGE_CURVE('E728',#1762,#1550,#1846,.T.);
#1848=ORIENTED_EDGE('',*,*,#1847,.T.);
#1849=ORIENTED_EDGE('',*,*,#1551,.F.);
#1850=EDGE_LOOP('',(#1841,#1842,#1848,#1849));
#1851=FACE_BOUND('',#1850,.T.);
#1852=ADVANCED_FACE('F821',(#1837,#1840,#1851),#1834,.T.);
#1853=CARTESIAN_POINT('',(-80.,-65.,0.));
#1854=DIRECTION('',(0.,1.,0.));
#1855=DIRECTION('',(1.,0.,0.));
#1856=AXIS2_PLACEMENT_3D('',#1853,#1854,#1855);
#1857=PLANE('',#1856);
#1858=ORIENTED_EDGE('',*,*,#1771,.F.);
#1859=ORIENTED_EDGE('',*,*,#1718,.T.);
#1860=ORIENTED_EDGE('',*,*,#1624,.T.);
#1861=ORIENTED_EDGE('',*,*,#1746,.F.);
#1862=ORIENTED_EDGE('',*,*,#1822,.F.);
#1863=ORIENTED_EDGE('',*,*,#1847,.F.);
#1864=EDGE_LOOP('',(#1858,#1859,#1860,#1861,#1862,#1863));
#1865=FACE_BOUND('',#1864,.T.);
#1866=ADVANCED_FACE('F735',(#1865),#1857,.F.);
#1867=CLOSED_SHELL('',(#35,#63,#80,#105,#138,#163,#196,#229,#262,#287,#320,#353,#378,#411,#444,
#464,#484,#501,#518,#538,#558,#575,#595,#612,#632,#649,#669,#686,#703,#720,#740,#760,#810,#896,
#921,#946,#971,#996,#1021,#1046,#1071,#1096,#1121,#1146,#1171,#1196,#1221,#1246,#1271,#1296,
#1321,#1354,#1387,#1429,#1471,#1504,#1537,#1563,#1610,#1641,#1728,#1751,#1775,#1829,#1852,#1866));
#1868=MANIFOLD_SOLID_BREP('B1',#1867);
#1869=ADVANCED_BREP_SHAPE_REPRESENTATION('',(#18,#1868),#14);
#1870=SHAPE_DEFINITION_REPRESENTATION(#9,#1869);
ENDSEC;
END-ISO-10303-21;
